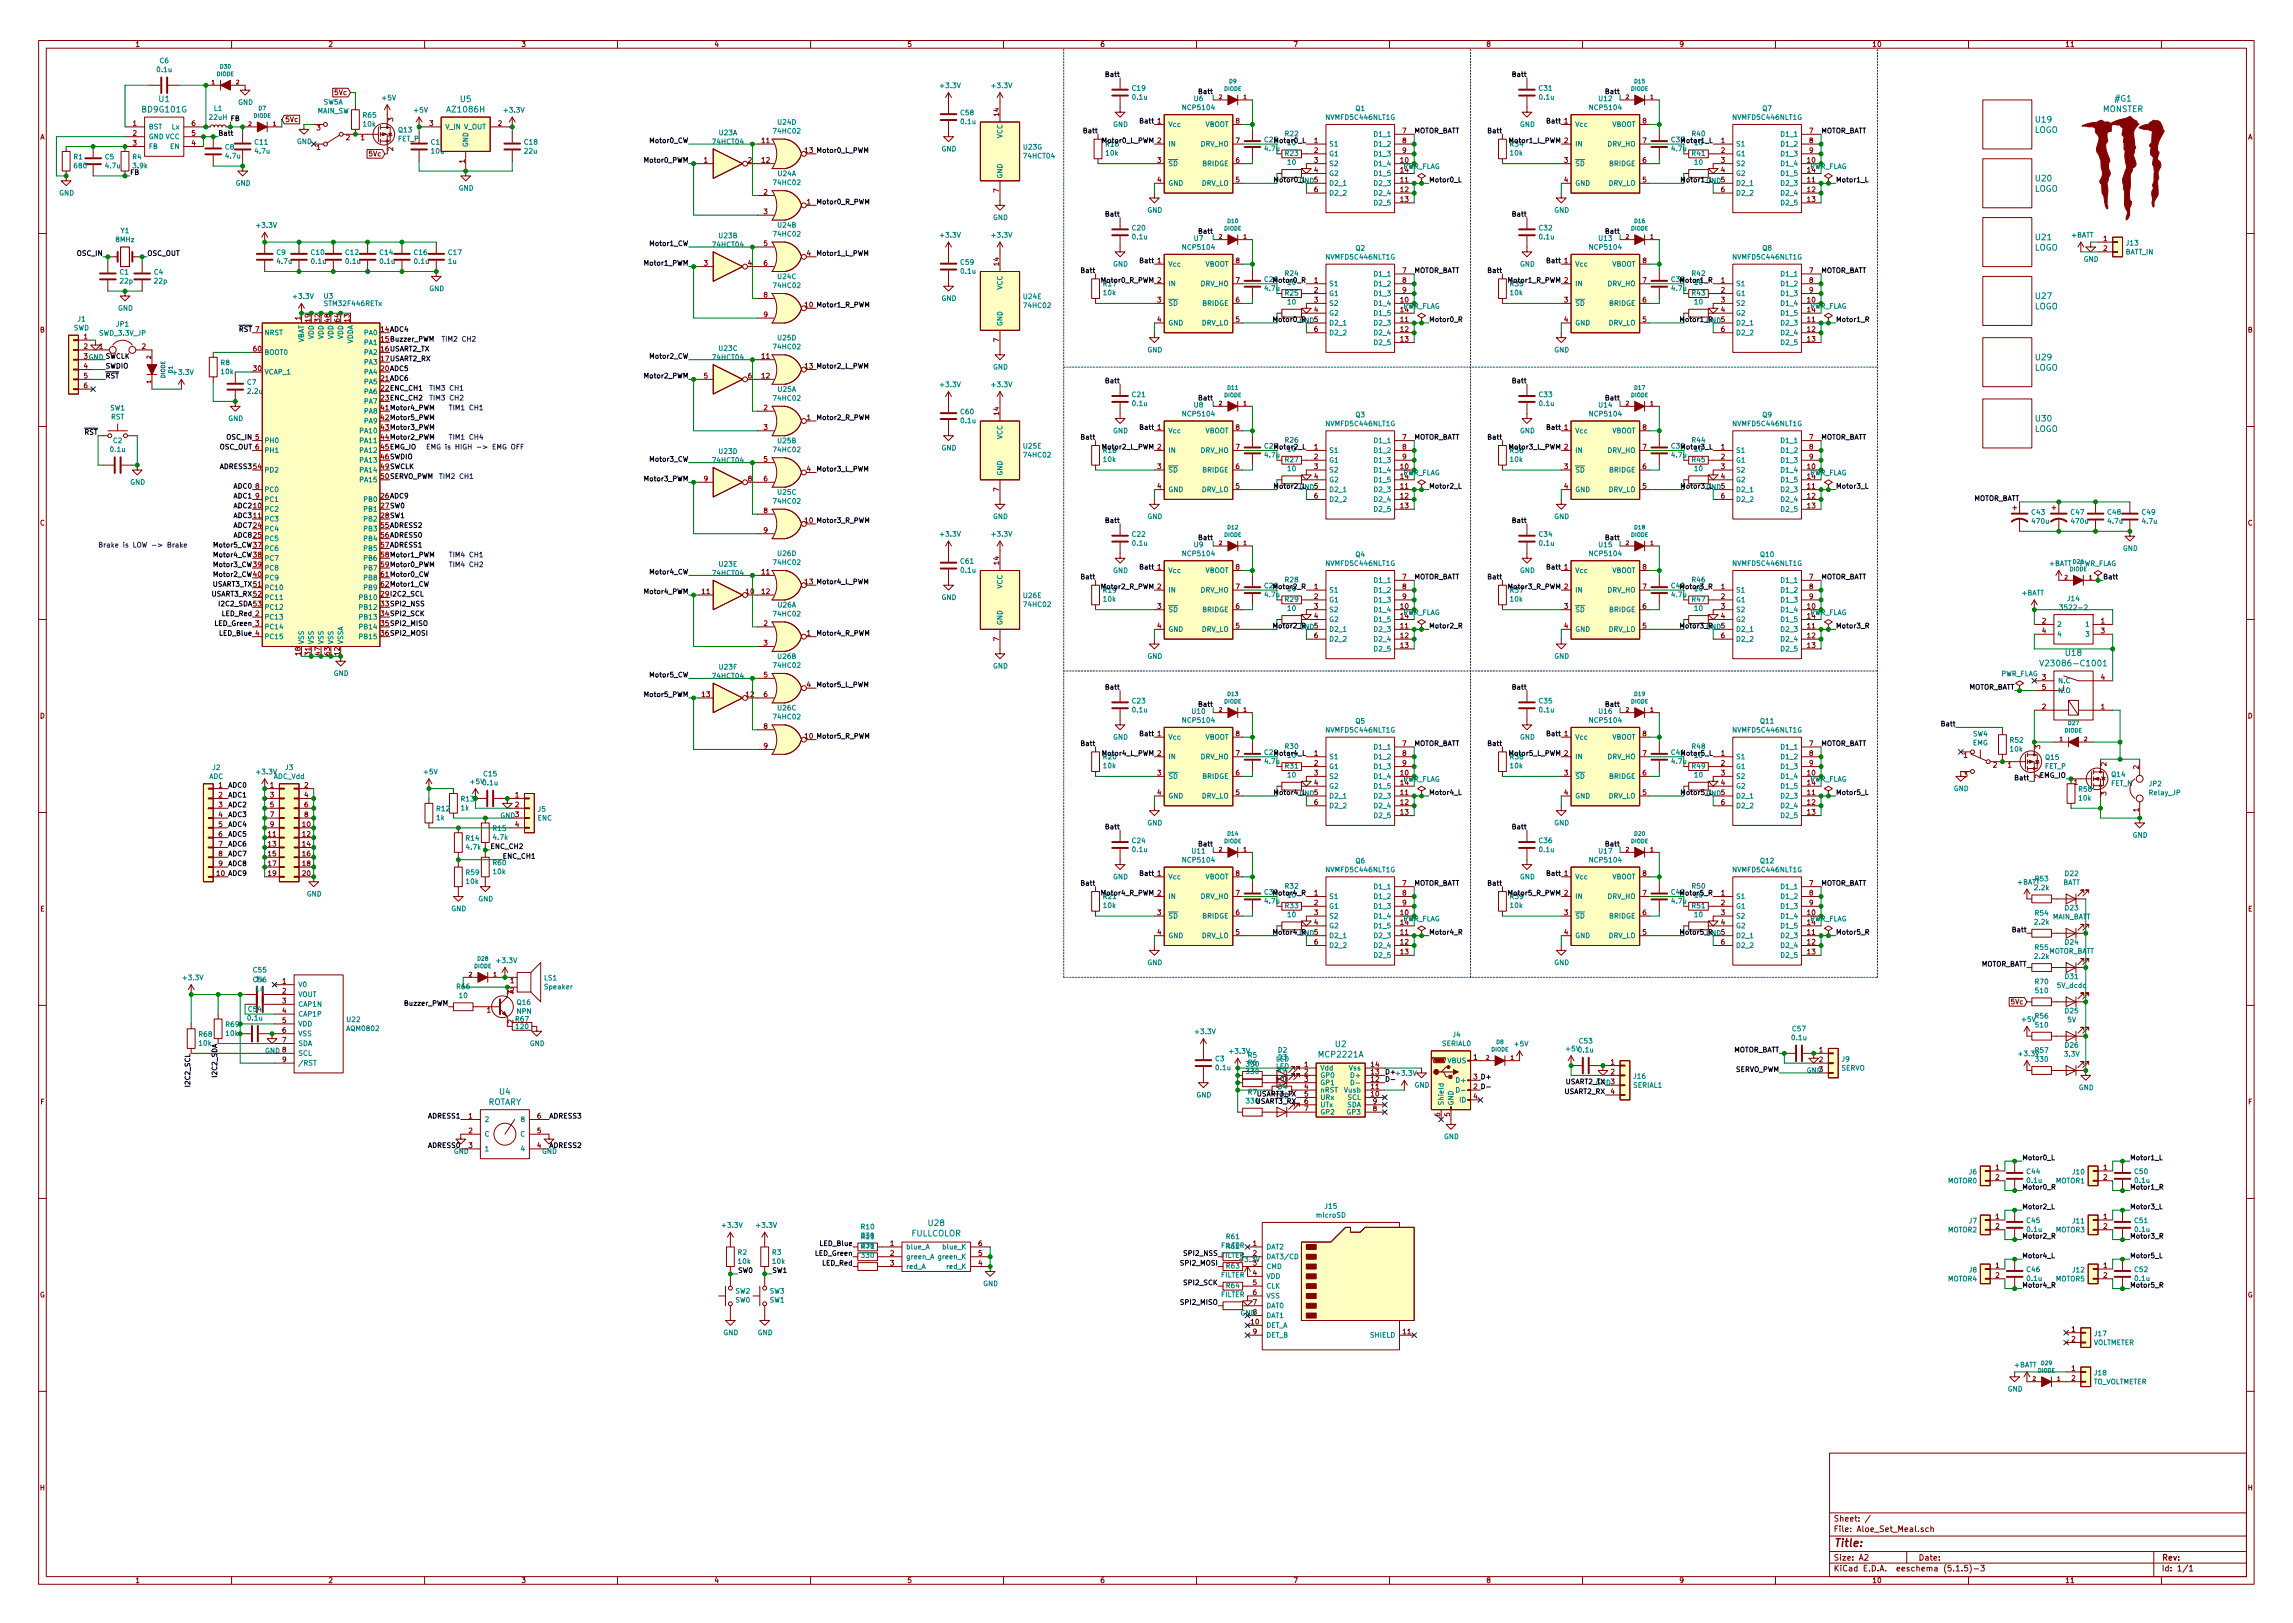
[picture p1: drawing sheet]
<svg xmlns="http://www.w3.org/2000/svg" width="297mm" height="210mm" viewBox="0 0 297 210" stroke-linecap="round" stroke-linejoin="round" font-family="sans-serif">
<defs><g id="words">
<text font-size="1.4" fill="#840000" x="237.5" y="200.4">Title:</text>
<g font-size="1.1" fill="#008484">
<text x="18.5" y="14.6">BD9G101G</text>
<text x="20.6" y="13.2">U1</text>
<text x="58.1" y="14.6">AZ1086H</text>
<text x="59.7" y="13.2">U5</text>
<text x="263.5" y="17.2">LOGO</text>
<text x="263.8" y="15.9">U19</text>
<text x="272.4" y="14.5">MONSTER</text>
<text x="274" y="13.2">#G1</text>
<text x="263.8" y="23.5">U20</text>
<text x="263.5" y="24.8">LOGO</text>
<text x="263.5" y="32.5">LOGO</text>
<text x="263.8" y="31.1">U21</text>
<text x="263.5" y="40.1">LOGO</text>
<text x="263.8" y="38.7">U27</text>
<text x="263.8" y="46.7">U29</text>
<text x="263.5" y="48">LOGO</text>
<text x="263.5" y="56">LOGO</text>
<text x="263.8" y="54.6">U30</text>
<text x="265" y="86.3">V23086-C1001</text>
<text x="267.6" y="85">U18</text>
<text x="170.9" y="137">MCP2221A</text>
<text x="173" y="135.6">U2</text>
<text x="63.2" y="143.1">ROTARY</text>
<text x="64.7" y="141.8">U4</text>
<text x="118" y="160.2">FULLCOLOR</text>
<text x="120.3" y="158.8">U28</text>
</g>
<g font-size="1" fill="#840000">
<text x="237.5" y="197.1">Sheet: /</text>
<text x="237.5" y="203.6">KiCad E.D.A. eeschema (5.1.5)-3</text>
<text x="237.5" y="202.2">Size: A2</text>
<text x="237.5" y="198.5">File: Aloe_Set_Meal.sch</text>
<text x="248.5" y="202.2">Date:</text>
<text x="280" y="202.2">Rev:</text>
<text x="280" y="203.6">Id: 1/1</text>
</g>
<g font-size=".9" fill="#840000">
<text x="17.5" y="6.1">1</text>
<text x="42.5" y="6.1">2</text>
<text x="67.5" y="6.1">3</text>
<text x="92.5" y="6.1">4</text>
<text x="117.5" y="6.1">5</text>
<text x="142.5" y="6.1">6</text>
<text x="167.5" y="6.1">7</text>
<text x="192.5" y="6.1">8</text>
<text x="217.5" y="6.1">9</text>
<text x="242.5" y="6.1">10</text>
<text x="267.5" y="6.1">11</text>
<text x="17.2" y="16.3">1</text>
<text x="17.2" y="17.6">2</text>
<text x="24.8" y="17.6">5</text>
<text x="24.8" y="16.3">6</text>
<text x="36.9" y="15.8">5Vc</text>
<text x="41" y="16.9">3</text>
<text x="43.4" y="12.3">5Vc</text>
<text x="50.9" y="15.7" transform="rotate(-90 50.9 15.7)">3</text>
<text x="55.6" y="16.3">3</text>
<text x="64.5" y="16.3">2</text>
<text x="129.4" y="15" transform="rotate(-90 129.4 15)">14</text>
<text x="160.1" y="16">8</text>
<text x="181.7" y="17.3">7</text>
<text x="212.8" y="16">8</text>
<text x="234.4" y="17.3">7</text>
<text x="5.2" y="18.1">A</text>
<text x="17.2" y="18.9">3</text>
<text x="24.8" y="18.9">4</text>
<text x="41" y="19.4">1</text>
<text x="44.8" y="18.2">2</text>
<text x="46.7" y="18.2">1</text>
<text x="47.9" y="20.3">5Vc</text>
<text x="50.9" y="19.5" transform="rotate(-90 50.9 19.5)">2</text>
<text x="60.2" y="21.1" transform="rotate(-90 60.2 21.1)">1</text>
<text x="91.2" y="21.1">1</text>
<text x="96.9" y="21.1">2</text>
<text x="98.7" y="18.5">11</text>
<text x="98.7" y="21.1">12</text>
<text x="149.9" y="18.5">2</text>
<text x="149.9" y="21.1">3</text>
<text x="149.9" y="23.6">4</text>
<text x="160.1" y="23.6">5</text>
<text x="160.1" y="21.1">6</text>
<text x="160.1" y="18.5">7</text>
<text x="170.3" y="18.5">1</text>
<text x="170.3" y="19.8">2</text>
<text x="170.3" y="21.1">3</text>
<text x="170.3" y="22.3">4</text>
<text x="181.4" y="21.1">10</text>
<text x="181.4" y="23.6">11</text>
<text x="181.4" y="22.3">14</text>
<text x="181.7" y="18.5">8</text>
<text x="181.7" y="19.8">9</text>
<text x="202.6" y="18.5">2</text>
<text x="202.6" y="21.1">3</text>
<text x="202.6" y="23.6">4</text>
<text x="212.8" y="23.6">5</text>
<text x="212.8" y="21.1">6</text>
<text x="212.8" y="18.5">7</text>
<text x="223" y="18.5">1</text>
<text x="223" y="19.8">2</text>
<text x="223" y="21.1">3</text>
<text x="223" y="22.3">4</text>
<text x="234.1" y="21.1">10</text>
<text x="234.1" y="23.6">11</text>
<text x="234.1" y="22.3">14</text>
<text x="234.4" y="18.5">8</text>
<text x="234.4" y="19.8">9</text>
<text x="291.2" y="18.1">A</text>
<text x="98.9" y="25.2">2</text>
<text x="98.9" y="27.7">3</text>
<text x="104.5" y="26.5">1</text>
<text x="129.4" y="24.9" transform="rotate(-90 129.4 24.9)">7</text>
<text x="170.3" y="24.9">6</text>
<text x="181.4" y="24.9">12</text>
<text x="181.4" y="26.2">13</text>
<text x="223" y="24.9">6</text>
<text x="234.1" y="24.9">12</text>
<text x="234.1" y="26.2">13</text>
<text x="91.2" y="34.4">3</text>
<text x="96.9" y="34.4">4</text>
<text x="98.9" y="31.9">5</text>
<text x="98.9" y="34.4">6</text>
<text x="104.5" y="33.1">4</text>
<text x="129.4" y="34.4" transform="rotate(-90 129.4 34.4)">14</text>
<text x="160.1" y="34.1">8</text>
<text x="181.7" y="35.4">7</text>
<text x="212.8" y="34.1">8</text>
<text x="234.4" y="35.4">7</text>
<text x="272.5" y="31.2">1</text>
<text x="272.5" y="32.5">2</text>
<text x="38.9" y="41.4" transform="rotate(-90 38.9 41.4)">1</text>
<text x="40.2" y="41.7" transform="rotate(-90 40.2 41.7)">19</text>
<text x="41.5" y="41.7" transform="rotate(-90 41.5 41.7)">32</text>
<text x="42.7" y="41.7" transform="rotate(-90 42.7 41.7)">48</text>
<text x="44" y="41.7" transform="rotate(-90 44 41.7)">64</text>
<text x="45.3" y="41.7" transform="rotate(-90 45.3 41.7)">13</text>
<text x="98.9" y="38.5">8</text>
<text x="98.9" y="41.1">9</text>
<text x="149.9" y="39.2">3</text>
<text x="149.9" y="41.7">4</text>
<text x="160.1" y="41.7">5</text>
<text x="160.1" y="39.2">6</text>
<text x="160.1" y="36.6">7</text>
<text x="170.3" y="36.6">1</text>
<text x="170.3" y="37.9">2</text>
<text x="170.3" y="39.2">3</text>
<text x="170.3" y="40.4">4</text>
<text x="181.4" y="39.2">10</text>
<text x="181.4" y="41.7">11</text>
<text x="181.4" y="40.4">14</text>
<text x="181.7" y="36.6">8</text>
<text x="181.7" y="37.9">9</text>
<text x="202.6" y="39.2">3</text>
<text x="202.6" y="41.7">4</text>
<text x="212.8" y="41.7">5</text>
<text x="212.8" y="39.2">6</text>
<text x="212.8" y="36.6">7</text>
<text x="223" y="36.6">1</text>
<text x="223" y="37.9">2</text>
<text x="223" y="39.2">3</text>
<text x="223" y="40.4">4</text>
<text x="234.1" y="39.2">10</text>
<text x="234.1" y="41.7">11</text>
<text x="234.1" y="40.4">14</text>
<text x="234.4" y="36.6">8</text>
<text x="234.4" y="37.9">9</text>
<text x="5.2" y="43.1">B</text>
<text x="10.9" y="43.9">1</text>
<text x="10.9" y="45.2">2</text>
<text x="10.9" y="47.7">4</text>
<text x="12.9" y="45.2">1</text>
<text x="18.4" y="45.2">2</text>
<text x="32.9" y="45.5">60</text>
<text x="98.7" y="46.5">11</text>
<text x="129.4" y="44.3" transform="rotate(-90 129.4 44.3)">7</text>
<text x="170.3" y="43">6</text>
<text x="181.4" y="43">12</text>
<text x="181.4" y="44.3">13</text>
<text x="223" y="43">6</text>
<text x="234.1" y="43">12</text>
<text x="234.1" y="44.3">13</text>
<text x="291.2" y="43.1">B</text>
<text x="10.9" y="49">5</text>
<text x="10.9" y="50.3">6</text>
<text x="32.9" y="48.1">30</text>
<text x="91.2" y="49">5</text>
<text x="96.9" y="49">6</text>
<text x="98.7" y="49">12</text>
<text x="98.9" y="53.1">2</text>
<text x="129.4" y="53.8" transform="rotate(-90 129.4 53.8)">14</text>
<text x="98.9" y="55.7">3</text>
<text x="98.9" y="59.8">5</text>
<text x="104.5" y="54.4">1</text>
<text x="149.9" y="58.2">2</text>
<text x="160.1" y="58.2">7</text>
<text x="160.1" y="55.7">8</text>
<text x="170.3" y="58.2">1</text>
<text x="170.3" y="59.5">2</text>
<text x="181.7" y="57">7</text>
<text x="181.7" y="58.2">8</text>
<text x="181.7" y="59.5">9</text>
<text x="202.6" y="58.2">2</text>
<text x="212.8" y="58.2">7</text>
<text x="212.8" y="55.7">8</text>
<text x="223" y="58.2">1</text>
<text x="223" y="59.5">2</text>
<text x="234.4" y="57">7</text>
<text x="234.4" y="58.2">8</text>
<text x="234.4" y="59.5">9</text>
<text x="32.9" y="65.8">10</text>
<text x="32.9" y="60.8">54</text>
<text x="33.1" y="63.3">8</text>
<text x="33.1" y="64.6">9</text>
<text x="91.2" y="62.4">9</text>
<text x="96.9" y="62.4">8</text>
<text x="98.9" y="62.4">6</text>
<text x="104.5" y="61.1">4</text>
<text x="129.4" y="63.7" transform="rotate(-90 129.4 63.7)">7</text>
<text x="149.9" y="60.8">3</text>
<text x="149.9" y="63.3">4</text>
<text x="160.1" y="63.3">5</text>
<text x="160.1" y="60.8">6</text>
<text x="170.3" y="60.8">3</text>
<text x="170.3" y="62">4</text>
<text x="170.3" y="64.6">6</text>
<text x="181.4" y="60.8">10</text>
<text x="181.4" y="63.3">11</text>
<text x="181.4" y="64.6">12</text>
<text x="181.4" y="65.8">13</text>
<text x="181.4" y="62">14</text>
<text x="202.6" y="60.8">3</text>
<text x="202.6" y="63.3">4</text>
<text x="212.8" y="63.3">5</text>
<text x="212.8" y="60.8">6</text>
<text x="223" y="60.8">3</text>
<text x="223" y="62">4</text>
<text x="223" y="64.6">6</text>
<text x="234.1" y="60.8">10</text>
<text x="234.1" y="63.3">11</text>
<text x="234.1" y="64.6">12</text>
<text x="234.1" y="65.8">13</text>
<text x="234.1" y="62">14</text>
<text x="5.2" y="68.1">C</text>
<text x="32.9" y="67.1">11</text>
<text x="32.9" y="68.4">24</text>
<text x="32.9" y="69.7">25</text>
<text x="98.9" y="66.5">8</text>
<text x="98.9" y="69">9</text>
<text x="291.2" y="68.1">C</text>
<text x="91" y="77">11</text>
<text x="96.7" y="77">10</text>
<text x="98.7" y="74.4">11</text>
<text x="98.7" y="77">12</text>
<text x="129.4" y="73.1" transform="rotate(-90 129.4 73.1)">14</text>
<text x="160.1" y="76.3">7</text>
<text x="160.1" y="73.8">8</text>
<text x="170.3" y="76.3">1</text>
<text x="170.3" y="77.6">2</text>
<text x="181.7" y="75.1">7</text>
<text x="181.7" y="76.3">8</text>
<text x="181.7" y="77.6">9</text>
<text x="212.8" y="76.3">7</text>
<text x="212.8" y="73.8">8</text>
<text x="223" y="76.3">1</text>
<text x="223" y="77.6">2</text>
<text x="234.4" y="75.1">7</text>
<text x="234.4" y="76.3">8</text>
<text x="234.4" y="77.6">9</text>
<text x="98.9" y="81.1">2</text>
<text x="98.9" y="83.6">3</text>
<text x="104.5" y="82.4">1</text>
<text x="129.4" y="83" transform="rotate(-90 129.4 83)">7</text>
<text x="149.9" y="78.9">3</text>
<text x="149.9" y="81.4">4</text>
<text x="160.1" y="81.4">5</text>
<text x="160.1" y="78.9">6</text>
<text x="170.3" y="78.9">3</text>
<text x="170.3" y="80.1">4</text>
<text x="170.3" y="82.7">6</text>
<text x="181.4" y="78.9">10</text>
<text x="181.4" y="81.4">11</text>
<text x="181.4" y="82.7">12</text>
<text x="181.4" y="83.9">13</text>
<text x="181.4" y="80.1">14</text>
<text x="202.6" y="78.9">3</text>
<text x="202.6" y="81.4">4</text>
<text x="212.8" y="81.4">5</text>
<text x="212.8" y="78.9">6</text>
<text x="223" y="78.9">3</text>
<text x="223" y="80.1">4</text>
<text x="223" y="82.7">6</text>
<text x="234.1" y="78.9">10</text>
<text x="234.1" y="81.4">11</text>
<text x="234.1" y="82.7">12</text>
<text x="234.1" y="83.9">13</text>
<text x="234.1" y="80.1">14</text>
<text x="264.6" y="80.8">2</text>
<text x="264.6" y="82">4</text>
<text x="272.2" y="80.8">1</text>
<text x="272.2" y="82">3</text>
<text x="38.9" y="84.9" transform="rotate(-90 38.9 84.9)">18</text>
<text x="40.2" y="84.9" transform="rotate(-90 40.2 84.9)">31</text>
<text x="41.5" y="84.9" transform="rotate(-90 41.5 84.9)">47</text>
<text x="42.7" y="84.9" transform="rotate(-90 42.7 84.9)">63</text>
<text x="44" y="84.9" transform="rotate(-90 44 84.9)">12</text>
<text x="98.9" y="87.8">5</text>
<text x="104.5" y="89">4</text>
<text x="264.6" y="88.1">3</text>
<text x="264.6" y="89.3">5</text>
<text x="272.2" y="88.1">4</text>
<text x="5.2" y="93.1">D</text>
<text x="91" y="90.3">13</text>
<text x="96.7" y="90.3">12</text>
<text x="98.9" y="90.3">6</text>
<text x="98.9" y="94.4">8</text>
<text x="160.1" y="95.4">8</text>
<text x="212.8" y="95.4">8</text>
<text x="264.6" y="91.9">2</text>
<text x="272.2" y="91.9">1</text>
<text x="291.2" y="93.1">D</text>
<text x="98.9" y="97">9</text>
<text x="149.9" y="97.9">2</text>
<text x="149.9" y="100.5">3</text>
<text x="160.1" y="100.5">6</text>
<text x="160.1" y="97.9">7</text>
<text x="170.3" y="97.9">1</text>
<text x="170.3" y="99.2">2</text>
<text x="170.3" y="100.5">3</text>
<text x="170.3" y="101.7">4</text>
<text x="181.4" y="100.5">10</text>
<text x="181.4" y="101.7">14</text>
<text x="181.7" y="96.6">7</text>
<text x="181.7" y="97.9">8</text>
<text x="181.7" y="99.2">9</text>
<text x="202.6" y="97.9">2</text>
<text x="202.6" y="100.5">3</text>
<text x="212.8" y="100.5">6</text>
<text x="212.8" y="97.9">7</text>
<text x="223" y="97.9">1</text>
<text x="223" y="99.2">2</text>
<text x="223" y="100.5">3</text>
<text x="223" y="101.7">4</text>
<text x="234.1" y="100.5">10</text>
<text x="234.1" y="101.7">14</text>
<text x="234.4" y="96.6">7</text>
<text x="234.4" y="97.9">8</text>
<text x="234.4" y="99.2">9</text>
<text x="254.4" y="98.2">1</text>
<text x="254.4" y="100.7">3</text>
<text x="258.2" y="99.4">2</text>
<text x="260.1" y="99.4">1</text>
<text x="264.3" y="97" transform="rotate(-90 264.3 97)">3</text>
<text x="268.7" y="101.7">1</text>
<text x="272.9" y="99.2" transform="rotate(-90 272.9 99.2)">2</text>
<text x="277.1" y="99.6" transform="rotate(-90 277.1 99.6)">2</text>
<text x="28.3" y="102">1</text>
<text x="28.3" y="103.3">2</text>
<text x="28.3" y="104.6">3</text>
<text x="28.3" y="105.8">4</text>
<text x="28.3" y="107.1">5</text>
<text x="35" y="102">1</text>
<text x="35" y="103.3">3</text>
<text x="35" y="104.6">5</text>
<text x="35" y="105.8">7</text>
<text x="35" y="107.1">9</text>
<text x="39.2" y="107.1">10</text>
<text x="39.4" y="102">2</text>
<text x="39.4" y="103.3">4</text>
<text x="39.4" y="104.6">6</text>
<text x="39.4" y="105.8">8</text>
<text x="66.8" y="103.3">1</text>
<text x="66.8" y="104.6">2</text>
<text x="66.8" y="107.1">4</text>
<text x="149.9" y="103">4</text>
<text x="160.1" y="103">5</text>
<text x="170.3" y="104.3">6</text>
<text x="181.4" y="103">11</text>
<text x="181.4" y="104.3">12</text>
<text x="181.4" y="105.5">13</text>
<text x="202.6" y="103">4</text>
<text x="212.8" y="103">5</text>
<text x="223" y="104.3">6</text>
<text x="234.1" y="103">11</text>
<text x="234.1" y="104.3">12</text>
<text x="234.1" y="105.5">13</text>
<text x="272.9" y="103" transform="rotate(-90 272.9 103)">3</text>
<text x="277.1" y="105.2" transform="rotate(-90 277.1 105.2)">1</text>
<text x="28.3" y="108.4">6</text>
<text x="28.3" y="109.7">7</text>
<text x="28.3" y="110.9">8</text>
<text x="28.3" y="112.2">9</text>
<text x="34.8" y="108.4">11</text>
<text x="34.8" y="109.7">13</text>
<text x="34.8" y="110.9">15</text>
<text x="34.8" y="112.2">17</text>
<text x="34.8" y="113.5">19</text>
<text x="39.2" y="108.4">12</text>
<text x="39.2" y="109.7">14</text>
<text x="39.2" y="110.9">16</text>
<text x="39.2" y="112.2">18</text>
<text x="39.2" y="113.5">20</text>
<text x="160.1" y="113.5">8</text>
<text x="212.8" y="113.5">8</text>
<text x="5.2" y="118.1">E</text>
<text x="149.9" y="118.5">3</text>
<text x="160.1" y="118.5">6</text>
<text x="160.1" y="116">7</text>
<text x="170.3" y="116">1</text>
<text x="170.3" y="117.3">2</text>
<text x="170.3" y="118.5">3</text>
<text x="170.3" y="119.8">4</text>
<text x="181.4" y="118.5">10</text>
<text x="181.4" y="119.8">14</text>
<text x="181.7" y="114.7">7</text>
<text x="181.7" y="116">8</text>
<text x="181.7" y="117.3">9</text>
<text x="202.6" y="118.5">3</text>
<text x="212.8" y="118.5">6</text>
<text x="212.8" y="116">7</text>
<text x="223" y="116">1</text>
<text x="223" y="117.3">2</text>
<text x="223" y="118.5">3</text>
<text x="223" y="119.8">4</text>
<text x="234.1" y="118.5">10</text>
<text x="234.1" y="119.8">14</text>
<text x="234.4" y="114.7">7</text>
<text x="234.4" y="116">8</text>
<text x="234.4" y="117.3">9</text>
<text x="291.2" y="118.1">E</text>
<text x="149.9" y="121.1">4</text>
<text x="160.1" y="121.1">5</text>
<text x="170.3" y="122.4">6</text>
<text x="181.4" y="121.1">11</text>
<text x="181.4" y="122.4">12</text>
<text x="181.4" y="123.6">13</text>
<text x="202.6" y="121.1">4</text>
<text x="212.8" y="121.1">5</text>
<text x="223" y="122.4">6</text>
<text x="234.1" y="121.1">11</text>
<text x="234.1" y="122.4">12</text>
<text x="234.1" y="123.6">13</text>
<text x="36.6" y="127.4">1</text>
<text x="36.6" y="128.7">2</text>
<text x="36.6" y="130">3</text>
<text x="36.6" y="131.2">4</text>
<text x="63.1" y="131.2">1</text>
<text x="66.1" y="127.4">1</text>
<text x="66.1" y="128.6">2</text>
<text x="66.5" y="128.8" transform="rotate(-90 66.5 128.8)">3</text>
<text x="260.6" y="130.1">5Vc</text>
<text x="34.3" y="136.5">GND 8</text>
<text x="36.6" y="132.5">5</text>
<text x="36.6" y="133.8">6</text>
<text x="36.6" y="135.1">7</text>
<text x="36.6" y="137.6">9</text>
<text x="66.5" y="132.6" transform="rotate(-90 66.5 132.6)">2</text>
<text x="190.9" y="137.3">1</text>
<text x="208.7" y="137.9">1</text>
<text x="235.7" y="136.3">1</text>
<text x="235.7" y="137.6">2</text>
<text x="5.2" y="143.1">F</text>
<text x="165.3" y="140.1">10k</text>
<text x="169" y="138.2">1</text>
<text x="169" y="139.2">2</text>
<text x="169" y="140.1">3</text>
<text x="169" y="141.1">4</text>
<text x="169" y="142">5</text>
<text x="169" y="143">6</text>
<text x="169" y="143.9">7</text>
<text x="177.6" y="142">10</text>
<text x="177.6" y="141.1">11</text>
<text x="177.6" y="140.1">12</text>
<text x="177.6" y="139.2">13</text>
<text x="177.6" y="138.2">14</text>
<text x="177.9" y="143.9">8</text>
<text x="177.9" y="143">9</text>
<text x="190.9" y="142.4">4</text>
<text x="208.7" y="139.2">2</text>
<text x="208.7" y="141.7">4</text>
<text x="291.2" y="143.1">F</text>
<text x="60.7" y="144.9">1</text>
<text x="60.7" y="146.8">2</text>
<text x="60.7" y="148.7">3</text>
<text x="69.6" y="148.7">4</text>
<text x="69.6" y="146.8">5</text>
<text x="69.6" y="144.9">6</text>
<text x="186.6" y="144.6" transform="rotate(-90 186.6 144.6)">6</text>
<text x="187.8" y="144.6" transform="rotate(-90 187.8 144.6)">5</text>
<text x="258.5" y="151.6">1</text>
<text x="258.5" y="152.8">2</text>
<text x="272.5" y="151.6">1</text>
<text x="272.5" y="152.8">2</text>
<text x="115.3" y="161.4">1</text>
<text x="126.8" y="161.4">6</text>
<text x="162.3" y="161.4">1</text>
<text x="258.5" y="157.9">1</text>
<text x="258.5" y="159.2">2</text>
<text x="272.5" y="157.9">1</text>
<text x="272.5" y="159.2">2</text>
<text x="115.3" y="162.7">2</text>
<text x="115.3" y="164">3</text>
<text x="126.8" y="164">4</text>
<text x="126.8" y="162.7">5</text>
<text x="162.3" y="162.7">2</text>
<text x="162.3" y="164">3</text>
<text x="162.3" y="165.2">4</text>
<text x="162.3" y="166.5">5</text>
<text x="162.3" y="167.8">6</text>
<text x="258.5" y="164.3">1</text>
<text x="258.5" y="165.5">2</text>
<text x="272.5" y="164.3">1</text>
<text x="272.5" y="165.5">2</text>
<text x="5.2" y="168.1">G</text>
<text x="162.1" y="171.6">10</text>
<text x="162.3" y="169">7</text>
<text x="162.3" y="172.8">9</text>
<text x="181.8" y="172.8">11</text>
<text x="268.4" y="172.5">1</text>
<text x="268.4" y="173.8">2</text>
<text x="291.2" y="168.1">G</text>
<text x="268.4" y="177.6">1</text>
<text x="268.4" y="178.9">2</text>
<text x="5.2" y="193.1">H</text>
<text x="291.2" y="193.1">H</text>
<text x="17.5" y="205.1">1</text>
<text x="42.5" y="205.1">2</text>
<text x="67.5" y="205.1">3</text>
<text x="92.5" y="205.1">4</text>
<text x="117.5" y="205.1">5</text>
<text x="142.5" y="205.1">6</text>
<text x="167.5" y="205.1">7</text>
<text x="192.5" y="205.1">8</text>
<text x="217.5" y="205.1">9</text>
<text x="242.5" y="205.1">10</text>
<text x="267.5" y="205.1">11</text>
</g>
<g font-size=".9" fill="#008484">
<text x="20.4" y="9.3">0.1u</text>
<text x="20.7" y="8.2">C6</text>
<text x="121.9" y="11.4">+3.3V</text>
<text x="128.6" y="11.4">+3.3V</text>
<text x="146.7" y="11.8">C19</text>
<text x="199.4" y="11.8">C31</text>
<text x="19.2" y="16.8">BST</text>
<text x="22.3" y="16.8">Lx</text>
<text x="27.7" y="14.4">L1</text>
<text x="30.8" y="13.6">GND</text>
<text x="41.1" y="14.7">MAIN_SW</text>
<text x="41.9" y="13.5">SW5A</text>
<text x="47.1" y="15.2">R65</text>
<text x="47.1" y="16.4">10k</text>
<text x="49.6" y="13">+5V</text>
<text x="51.7" y="17.2">Q13</text>
<text x="53.7" y="14.6">+5V</text>
<text x="57.7" y="16.8">V_IN V_OUT</text>
<text x="65.4" y="14.6">+3.3V</text>
<text x="93.2" y="17.5">U23A</text>
<text x="100.3" y="17.3">74HC02</text>
<text x="100.8" y="16.1">U24D</text>
<text x="124.5" y="14.9">C58</text>
<text x="124.5" y="16.1">0.1u</text>
<text x="129.9" y="17.9" transform="rotate(-90 129.9 17.9)">VCC</text>
<text x="144.2" y="16.4">GND</text>
<text x="146.8" y="12.9">0.1u</text>
<text x="151.3" y="16.4">Vcc</text>
<text x="153.3" y="14.3">NCP5104</text>
<text x="154.7" y="13.1">U6</text>
<text x="156" y="16.4">VBOOT</text>
<text x="166.5" y="17.6">R22</text>
<text x="171.9" y="15.5">NVMFD5C446NLT1G</text>
<text x="175.6" y="14.4">Q1</text>
<text x="178.2" y="17.7">D1_1</text>
<text x="196.9" y="16.4">GND</text>
<text x="199.5" y="12.9">0.1u</text>
<text x="204" y="16.4">Vcc</text>
<text x="206" y="14.3">NCP5104</text>
<text x="207.1" y="13.1">U12</text>
<text x="208.7" y="16.4">VBOOT</text>
<text x="219.2" y="17.6">R40</text>
<text x="224.6" y="15.5">NVMFD5C446NLT1G</text>
<text x="228.3" y="14.4">Q7</text>
<text x="230.9" y="17.7">D1_1</text>
<text x="9.6" y="20.6">R1</text>
<text x="9.7" y="21.8">680</text>
<text x="13.6" y="20.6">C5</text>
<text x="13.7" y="21.8">4.7u</text>
<text x="17.2" y="20.6">R4</text>
<text x="17.3" y="21.8">3.9k</text>
<text x="19.2" y="18">GND VCC</text>
<text x="19.2" y="19.3">FB</text>
<text x="22.1" y="19.3">EN</text>
<text x="29.2" y="19.4">C8</text>
<text x="29.3" y="20.5">4.7u</text>
<text x="33" y="18.7">C11</text>
<text x="33.1" y="19.9">4.7u</text>
<text x="38.5" y="18.7">GND</text>
<text x="51.5" y="18.3">FET_P</text>
<text x="55.9" y="18.7">C13</text>
<text x="55.9" y="19.9">10u</text>
<text x="60.6" y="19.1" transform="rotate(-90 60.6 19.1)">GND</text>
<text x="68" y="18.7">C18</text>
<text x="68" y="19.9">22u</text>
<text x="92.4" y="18.7">74HCT04</text>
<text x="100.3" y="24">74HC02</text>
<text x="100.8" y="22.8">U24A</text>
<text x="122" y="19.6">GND</text>
<text x="129.9" y="23.2" transform="rotate(-90 129.9 23.2)">GND</text>
<text x="132.6" y="19.4">U23G</text>
<text x="132.7" y="20.5">74HCT04</text>
<text x="143.3" y="20.1">10k</text>
<text x="151.3" y="19">IN</text>
<text x="151.3" y="21.5">SD</text>
<text x="155.5" y="19">DRV_HO</text>
<text x="155.8" y="21.5">BRIDGE</text>
<text x="163.9" y="19.6">4.7u</text>
<text x="166.5" y="20.2">R23</text>
<text x="166.8" y="21.3">10</text>
<text x="172.1" y="19">S1</text>
<text x="172.1" y="20.3">G1</text>
<text x="172.1" y="21.5">S2</text>
<text x="172.1" y="22.8">G2</text>
<text x="178.2" y="21.5">D1_4</text>
<text x="178.2" y="19">D1_2</text>
<text x="178.2" y="20.3">D1_3</text>
<text x="178.2" y="22.8">D1_5</text>
<text x="195.7" y="20.1">10k</text>
<text x="204" y="19">IN</text>
<text x="204" y="21.5">SD</text>
<text x="208.2" y="19">DRV_HO</text>
<text x="208.5" y="21.5">BRIDGE</text>
<text x="216.6" y="19.6">4.7u</text>
<text x="219.2" y="20.2">R41</text>
<text x="219.5" y="21.3">10</text>
<text x="224.9" y="19">S1</text>
<text x="224.9" y="20.3">G1</text>
<text x="224.9" y="21.5">S2</text>
<text x="224.9" y="22.8">G2</text>
<text x="230.9" y="21.5">D1_4</text>
<text x="230.9" y="19">D1_2</text>
<text x="230.9" y="20.3">D1_3</text>
<text x="230.9" y="22.8">D1_5</text>
<text x="7.7" y="25.3">GND</text>
<text x="30.5" y="24.1">GND</text>
<text x="33.3" y="29.5">+3.3V</text>
<text x="59.4" y="24.7">GND</text>
<text x="100.8" y="29.5">U24B</text>
<text x="128.6" y="28.5">GND</text>
<text x="146.7" y="29.9">C20</text>
<text x="148.6" y="27.6">GND</text>
<text x="151.3" y="24.1">GND</text>
<text x="155.6" y="24.1">DRV_LO</text>
<text x="172.1" y="24.1">D2_1</text>
<text x="172.1" y="25.3">D2_2</text>
<text x="178.2" y="24.1">D2_3</text>
<text x="178.2" y="25.3">D2_4</text>
<text x="178.2" y="26.6">D2_5</text>
<text x="199.4" y="29.9">C32</text>
<text x="201.3" y="27.6">GND</text>
<text x="204" y="24.1">GND</text>
<text x="208.3" y="24.1">DRV_LO</text>
<text x="224.9" y="24.1">D2_1</text>
<text x="224.9" y="25.3">D2_2</text>
<text x="230.9" y="24.1">D2_3</text>
<text x="230.9" y="25.3">D2_4</text>
<text x="230.9" y="26.6">D2_5</text>
<text x="15" y="31.4">8MHz</text>
<text x="15.5" y="35.6">C1</text>
<text x="15.7" y="30.2">Y1</text>
<text x="20" y="35.6">C4</text>
<text x="35.9" y="33">C9</text>
<text x="36" y="34.2">4.7u</text>
<text x="40.3" y="33">C10</text>
<text x="40.4" y="34.2">0.1u</text>
<text x="44.8" y="33">C12</text>
<text x="44.8" y="34.2">0.1u</text>
<text x="49.2" y="33">C14</text>
<text x="49.3" y="34.2">0.1u</text>
<text x="53.7" y="33">C16</text>
<text x="53.7" y="34.2">0.1u</text>
<text x="58.1" y="34.2">1u</text>
<text x="58.1" y="33">C17</text>
<text x="92.4" y="32">74HCT04</text>
<text x="93.2" y="30.9">U23B</text>
<text x="100.3" y="30.6">74HC02</text>
<text x="121.9" y="30.8">+3.3V</text>
<text x="124.5" y="34.3">C59</text>
<text x="124.5" y="35.5">0.1u</text>
<text x="128.6" y="30.8">+3.3V</text>
<text x="144.2" y="34.5">GND</text>
<text x="146.8" y="31">0.1u</text>
<text x="151.3" y="34.5">Vcc</text>
<text x="153.3" y="32.4">NCP5104</text>
<text x="154.7" y="31.2">U7</text>
<text x="156" y="34.5">VBOOT</text>
<text x="166.5" y="35.7">R24</text>
<text x="171.9" y="33.6">NVMFD5C446NLT1G</text>
<text x="175.6" y="32.5">Q2</text>
<text x="178.2" y="35.8">D1_1</text>
<text x="196.9" y="34.5">GND</text>
<text x="199.5" y="31">0.1u</text>
<text x="204" y="34.5">Vcc</text>
<text x="206" y="32.4">NCP5104</text>
<text x="207.1" y="31.2">U13</text>
<text x="208.7" y="34.5">VBOOT</text>
<text x="219.2" y="35.7">R42</text>
<text x="224.6" y="33.6">NVMFD5C446NLT1G</text>
<text x="228.3" y="32.5">Q8</text>
<text x="230.9" y="35.8">D1_1</text>
<text x="268.3" y="30.8">+BATT</text>
<text x="269.9" y="33.9">GND</text>
<text x="275.3" y="33">BATT_IN</text>
<text x="275.5" y="31.8">J13</text>
<text x="10.1" y="41.7">J1</text>
<text x="15.3" y="40.3">GND</text>
<text x="15.6" y="36.7">22p</text>
<text x="20" y="36.7">22p</text>
<text x="38.1" y="38.7">+3.3V</text>
<text x="42" y="38.7">U3</text>
<text x="42.2" y="39.6">STM32F446RETx</text>
<text x="55.6" y="37.7">GND</text>
<text x="100.3" y="37.3">74HC02</text>
<text x="100.8" y="36.2">U24C</text>
<text x="122" y="39">GND</text>
<text x="129.9" y="37.5" transform="rotate(-90 129.9 37.5)">VCC</text>
<text x="132.6" y="38.7">U24E</text>
<text x="132.7" y="39.9">74HC02</text>
<text x="143" y="38.2">10k</text>
<text x="151.3" y="37.1">IN</text>
<text x="151.3" y="39.6">SD</text>
<text x="155.5" y="37.1">DRV_HO</text>
<text x="155.8" y="39.6">BRIDGE</text>
<text x="163.9" y="37.7">4.7u</text>
<text x="166.5" y="38.3">R25</text>
<text x="166.8" y="39.4">10</text>
<text x="172.1" y="37.1">S1</text>
<text x="172.1" y="38.3">G1</text>
<text x="172.1" y="39.6">S2</text>
<text x="172.1" y="40.9">G2</text>
<text x="178.2" y="39.6">D1_4</text>
<text x="178.2" y="37.1">D1_2</text>
<text x="178.2" y="38.3">D1_3</text>
<text x="178.2" y="40.9">D1_5</text>
<text x="195.7" y="38.2">10k</text>
<text x="204" y="37.1">IN</text>
<text x="204" y="39.6">SD</text>
<text x="208.2" y="37.1">DRV_HO</text>
<text x="208.5" y="39.6">BRIDGE</text>
<text x="216.6" y="37.7">4.7u</text>
<text x="219.2" y="38.3">R43</text>
<text x="219.5" y="39.4">10</text>
<text x="224.9" y="37.1">S1</text>
<text x="224.9" y="38.3">G1</text>
<text x="224.9" y="39.6">S2</text>
<text x="224.9" y="40.9">G2</text>
<text x="230.9" y="39.6">D1_4</text>
<text x="230.9" y="37.1">D1_2</text>
<text x="230.9" y="38.3">D1_3</text>
<text x="230.9" y="40.9">D1_5</text>
<text x="9.5" y="42.8">SWD</text>
<text x="12.9" y="43.5">SWD_3.3V_JP</text>
<text x="15.1" y="42.3">JP1</text>
<text x="28.6" y="47.3">R8</text>
<text x="34.2" y="46">BOOT0</text>
<text x="34.2" y="43.4">NRST</text>
<text x="39.4" y="44.5" transform="rotate(-90 39.4 44.5)">VBAT</text>
<text x="40.6" y="44" transform="rotate(-90 40.6 44)">VDD</text>
<text x="41.9" y="44" transform="rotate(-90 41.9 44)">VDD</text>
<text x="43.2" y="44" transform="rotate(-90 43.2 44)">VDD</text>
<text x="44.4" y="44" transform="rotate(-90 44.4 44)">VDD</text>
<text x="45.7" y="44.6" transform="rotate(-90 45.7 44.6)">VDDA</text>
<text x="47.2" y="43.4">PA0</text>
<text x="47.2" y="44.7">PA1</text>
<text x="47.2" y="46">PA2</text>
<text x="47.2" y="47.2">PA3</text>
<text x="92.4" y="46.6">74HCT04</text>
<text x="93.2" y="45.5">U23C</text>
<text x="100.3" y="45.2">74HC02</text>
<text x="100.8" y="44.1">U25D</text>
<text x="128.6" y="47.9">GND</text>
<text x="129.9" y="42.3" transform="rotate(-90 129.9 42.3)">GND</text>
<text x="148.6" y="45.7">GND</text>
<text x="151.3" y="42.2">GND</text>
<text x="155.6" y="42.2">DRV_LO</text>
<text x="172.1" y="42.2">D2_1</text>
<text x="172.1" y="43.4">D2_2</text>
<text x="178.2" y="42.2">D2_3</text>
<text x="178.2" y="43.4">D2_4</text>
<text x="178.2" y="44.7">D2_5</text>
<text x="201.3" y="45.7">GND</text>
<text x="204" y="42.2">GND</text>
<text x="208.3" y="42.2">DRV_LO</text>
<text x="224.9" y="42.2">D2_1</text>
<text x="224.9" y="43.4">D2_2</text>
<text x="230.9" y="42.2">D2_3</text>
<text x="230.9" y="43.4">D2_4</text>
<text x="230.9" y="44.7">D2_5</text>
<text x="14.3" y="53.2">SW1</text>
<text x="22.5" y="48.6">+3.3V</text>
<text x="28.7" y="48.5">10k</text>
<text x="32" y="49.9">C7</text>
<text x="32.1" y="51">2.2u</text>
<text x="34.2" y="48.5">VCAP_1</text>
<text x="47.2" y="48.5">PA4</text>
<text x="47.2" y="49.8">PA5</text>
<text x="47.2" y="51">PA6</text>
<text x="47.2" y="52.3">PA7</text>
<text x="47.2" y="53.6">PA8</text>
<text x="100.3" y="51.9">74HC02</text>
<text x="100.8" y="50.8">U25A</text>
<text x="121.9" y="50.1">+3.3V</text>
<text x="124.5" y="53.7">C60</text>
<text x="128.6" y="50.1">+3.3V</text>
<text x="146.7" y="51.4">C21</text>
<text x="146.8" y="52.6">0.1u</text>
<text x="153.3" y="53.9">NCP5104</text>
<text x="154.7" y="52.8">U8</text>
<text x="199.4" y="51.4">C33</text>
<text x="199.5" y="52.6">0.1u</text>
<text x="206" y="53.9">NCP5104</text>
<text x="207.1" y="52.8">U14</text>
<text x="14.4" y="54.3">RST</text>
<text x="14.4" y="58.6">0.1u</text>
<text x="14.7" y="57.4">C2</text>
<text x="29.6" y="54.5">GND</text>
<text x="34.2" y="57.4">PH0</text>
<text x="34.2" y="58.7">PH1</text>
<text x="46.7" y="56.1">PA10</text>
<text x="46.7" y="57.4">PA11</text>
<text x="46.7" y="58.7">PA12</text>
<text x="46.7" y="59.9">PA13</text>
<text x="47.2" y="54.9">PA9</text>
<text x="92.4" y="60">74HCT04</text>
<text x="93.2" y="58.8">U23D</text>
<text x="100.3" y="58.6">74HC02</text>
<text x="100.8" y="57.4">U25B</text>
<text x="122" y="58.4">GND</text>
<text x="124.5" y="54.8">0.1u</text>
<text x="129.9" y="56.9" transform="rotate(-90 129.9 56.9)">VCC</text>
<text x="132.6" y="58.1">U25E</text>
<text x="132.7" y="59.3">74HC02</text>
<text x="143" y="59.8">10k</text>
<text x="144.2" y="56.1">GND</text>
<text x="151.3" y="56.1">Vcc</text>
<text x="151.3" y="58.7">IN</text>
<text x="155.5" y="58.7">DRV_HO</text>
<text x="156" y="56.1">VBOOT</text>
<text x="163.9" y="59.3">4.7u</text>
<text x="166.5" y="59.9">R27</text>
<text x="166.5" y="57.3">R26</text>
<text x="171.9" y="55.2">NVMFD5C446NLT1G</text>
<text x="172.1" y="58.7">S1</text>
<text x="172.1" y="59.9">G1</text>
<text x="175.6" y="54.1">Q3</text>
<text x="178.2" y="57.4">D1_1</text>
<text x="178.2" y="58.7">D1_2</text>
<text x="178.2" y="59.9">D1_3</text>
<text x="195.7" y="59.8">10k</text>
<text x="196.9" y="56.1">GND</text>
<text x="204" y="56.1">Vcc</text>
<text x="204" y="58.7">IN</text>
<text x="208.2" y="58.7">DRV_HO</text>
<text x="208.7" y="56.1">VBOOT</text>
<text x="216.6" y="59.3">4.7u</text>
<text x="219.2" y="59.9">R45</text>
<text x="219.2" y="57.3">R44</text>
<text x="224.6" y="55.2">NVMFD5C446NLT1G</text>
<text x="224.9" y="58.7">S1</text>
<text x="224.9" y="59.9">G1</text>
<text x="228.3" y="54.1">Q9</text>
<text x="230.9" y="57.4">D1_1</text>
<text x="230.9" y="58.7">D1_2</text>
<text x="230.9" y="59.9">D1_3</text>
<text x="16.9" y="62.8">GND</text>
<text x="34.2" y="63.7">PC0</text>
<text x="34.2" y="65">PC1</text>
<text x="34.2" y="61.2">PD2</text>
<text x="46.7" y="61.2">PA14</text>
<text x="46.7" y="62.5">PA15</text>
<text x="47.2" y="65">PB0</text>
<text x="100.3" y="65.2">74HC02</text>
<text x="100.8" y="64.1">U25C</text>
<text x="129.9" y="61.7" transform="rotate(-90 129.9 61.7)">GND</text>
<text x="151.3" y="61.2">SD</text>
<text x="151.3" y="63.7">GND</text>
<text x="155.6" y="63.7">DRV_LO</text>
<text x="155.8" y="61.2">BRIDGE</text>
<text x="166.8" y="61">10</text>
<text x="172.1" y="61.2">S2</text>
<text x="172.1" y="62.5">G2</text>
<text x="172.1" y="63.7">D2_1</text>
<text x="172.1" y="65">D2_2</text>
<text x="178.2" y="61.2">D1_4</text>
<text x="178.2" y="63.7">D2_3</text>
<text x="178.2" y="65">D2_4</text>
<text x="178.2" y="62.5">D1_5</text>
<text x="204" y="61.2">SD</text>
<text x="204" y="63.7">GND</text>
<text x="208.3" y="63.7">DRV_LO</text>
<text x="208.5" y="61.2">BRIDGE</text>
<text x="219.5" y="61">10</text>
<text x="224.9" y="61.2">S2</text>
<text x="224.9" y="62.5">G2</text>
<text x="224.9" y="63.7">D2_1</text>
<text x="224.9" y="65">D2_2</text>
<text x="230.9" y="61.2">D1_4</text>
<text x="230.9" y="63.7">D2_3</text>
<text x="230.9" y="65">D2_4</text>
<text x="230.9" y="62.5">D1_5</text>
<text x="34.2" y="66.3">PC2</text>
<text x="34.2" y="67.6">PC3</text>
<text x="34.2" y="68.8">PC4</text>
<text x="34.2" y="70.1">PC5</text>
<text x="34.2" y="71.4">PC6</text>
<text x="47.2" y="66.3">PB1</text>
<text x="47.2" y="67.6">PB2</text>
<text x="47.2" y="68.8">PB3</text>
<text x="47.2" y="70.1">PB4</text>
<text x="47.2" y="71.4">PB5</text>
<text x="121.9" y="69.5">+3.3V</text>
<text x="128.6" y="69.5">+3.3V</text>
<text x="128.6" y="67.2">GND</text>
<text x="146.7" y="69.5">C22</text>
<text x="146.8" y="70.7">0.1u</text>
<text x="148.6" y="67.2">GND</text>
<text x="154.7" y="70.9">U9</text>
<text x="178.2" y="66.3">D2_5</text>
<text x="199.4" y="69.5">C34</text>
<text x="199.5" y="70.7">0.1u</text>
<text x="201.3" y="67.2">GND</text>
<text x="207.1" y="70.9">U15</text>
<text x="230.9" y="66.3">D2_5</text>
<text x="263.2" y="66.7">C43</text>
<text x="263.3" y="67.8">470u</text>
<text x="268.3" y="66.7">C47</text>
<text x="268.4" y="67.8">470u</text>
<text x="273.1" y="66.7">C48</text>
<text x="273.1" y="67.8">4.7u</text>
<text x="275" y="71.4">GND</text>
<text x="277.5" y="66.7">C49</text>
<text x="277.6" y="67.8">4.7u</text>
<text x="34.2" y="76.4">PC10</text>
<text x="34.2" y="77.7">PC11</text>
<text x="34.2" y="72.6">PC7</text>
<text x="34.2" y="73.9">PC8</text>
<text x="34.2" y="75.2">PC9</text>
<text x="46.7" y="77.7">PB10</text>
<text x="47.2" y="72.6">PB6</text>
<text x="47.2" y="73.9">PB7</text>
<text x="47.2" y="75.2">PB8</text>
<text x="47.2" y="76.4">PB9</text>
<text x="92.4" y="74.6">74HCT04</text>
<text x="93.2" y="73.4">U23E</text>
<text x="100.3" y="73.2">74HC02</text>
<text x="100.8" y="72">U26D</text>
<text x="122" y="77.7">GND</text>
<text x="124.5" y="73">C61</text>
<text x="124.5" y="74.2">0.1u</text>
<text x="129.9" y="76.3" transform="rotate(-90 129.9 76.3)">VCC</text>
<text x="132.6" y="77.5">U26E</text>
<text x="143" y="77.9">10k</text>
<text x="144.2" y="74.2">GND</text>
<text x="151.3" y="74.2">Vcc</text>
<text x="151.3" y="76.8">IN</text>
<text x="153.3" y="72">NCP5104</text>
<text x="155.5" y="76.8">DRV_HO</text>
<text x="156" y="74.2">VBOOT</text>
<text x="163.9" y="77.4">4.7u</text>
<text x="166.5" y="75.4">R28</text>
<text x="166.5" y="78">R29</text>
<text x="171.9" y="73.3">NVMFD5C446NLT1G</text>
<text x="172.1" y="76.8">S1</text>
<text x="175.6" y="72.2">Q4</text>
<text x="178.2" y="75.5">D1_1</text>
<text x="178.2" y="76.8">D1_2</text>
<text x="195.7" y="77.9">10k</text>
<text x="196.9" y="74.2">GND</text>
<text x="204" y="74.2">Vcc</text>
<text x="204" y="76.8">IN</text>
<text x="206" y="72">NCP5104</text>
<text x="208.2" y="76.8">DRV_HO</text>
<text x="208.7" y="74.2">VBOOT</text>
<text x="216.6" y="77.4">4.7u</text>
<text x="219.2" y="75.4">R46</text>
<text x="219.2" y="78">R47</text>
<text x="224.6" y="73.3">NVMFD5C446NLT1G</text>
<text x="224.9" y="76.8">S1</text>
<text x="228.1" y="72.2">Q10</text>
<text x="230.9" y="75.5">D1_1</text>
<text x="230.9" y="76.8">D1_2</text>
<text x="261.9" y="77.1">+BATT</text>
<text x="265.5" y="73.3">+BATT</text>
<text x="267.9" y="77.9">J14</text>
<text x="269.3" y="73.3">PWR_FLAG</text>
<text x="34.2" y="79">PC12</text>
<text x="34.2" y="80.3">PC13</text>
<text x="34.2" y="81.5">PC14</text>
<text x="34.2" y="82.8">PC15</text>
<text x="39.4" y="83.5" transform="rotate(-90 39.4 83.5)">VSS</text>
<text x="40.6" y="83.5" transform="rotate(-90 40.6 83.5)">VSS</text>
<text x="41.9" y="83.5" transform="rotate(-90 41.9 83.5)">VSS</text>
<text x="43.2" y="83.5" transform="rotate(-90 43.2 83.5)">VSS</text>
<text x="44.4" y="83.5" transform="rotate(-90 44.4 83.5)">VSSA</text>
<text x="46.7" y="79">PB12</text>
<text x="46.7" y="80.3">PB13</text>
<text x="46.7" y="81.5">PB14</text>
<text x="46.7" y="82.8">PB15</text>
<text x="100.3" y="79.9">74HC02</text>
<text x="100.8" y="78.7">U26A</text>
<text x="129.9" y="81" transform="rotate(-90 129.9 81)">GND</text>
<text x="132.7" y="78.6">74HC02</text>
<text x="151.3" y="79.3">SD</text>
<text x="151.3" y="81.8">GND</text>
<text x="155.6" y="81.8">DRV_LO</text>
<text x="155.8" y="79.3">BRIDGE</text>
<text x="166.8" y="79.1">10</text>
<text x="172.1" y="78">G1</text>
<text x="172.1" y="79.3">S2</text>
<text x="172.1" y="80.6">G2</text>
<text x="172.1" y="81.8">D2_1</text>
<text x="172.1" y="83.1">D2_2</text>
<text x="178.2" y="79.3">D1_4</text>
<text x="178.2" y="81.8">D2_3</text>
<text x="178.2" y="83.1">D2_4</text>
<text x="178.2" y="78">D1_3</text>
<text x="178.2" y="80.6">D1_5</text>
<text x="204" y="79.3">SD</text>
<text x="204" y="81.8">GND</text>
<text x="208.3" y="81.8">DRV_LO</text>
<text x="208.5" y="79.3">BRIDGE</text>
<text x="219.5" y="79.1">10</text>
<text x="224.9" y="78">G1</text>
<text x="224.9" y="79.3">S2</text>
<text x="224.9" y="80.6">G2</text>
<text x="224.9" y="81.8">D2_1</text>
<text x="224.9" y="83.1">D2_2</text>
<text x="230.9" y="79.3">D1_4</text>
<text x="230.9" y="81.8">D2_3</text>
<text x="230.9" y="83.1">D2_4</text>
<text x="230.9" y="78">D1_3</text>
<text x="230.9" y="80.6">D1_5</text>
<text x="266.4" y="81.2">2</text>
<text x="266.4" y="82.5">4</text>
<text x="267.2" y="79">3522-2</text>
<text x="270.3" y="81.2">1</text>
<text x="270.3" y="82.5">3</text>
<text x="43.2" y="87.6">GND</text>
<text x="92.4" y="87.9">74HCT04</text>
<text x="93.2" y="86.7">U23F</text>
<text x="100.3" y="86.5">74HC02</text>
<text x="100.8" y="85.4">U26B</text>
<text x="128.6" y="86.6">GND</text>
<text x="148.6" y="85.3">GND</text>
<text x="178.2" y="84.4">D2_5</text>
<text x="201.3" y="85.3">GND</text>
<text x="230.9" y="84.4">D2_5</text>
<text x="259.1" y="87.6">PWR_FLAG</text>
<text x="266.6" y="88.5">N.C</text>
<text x="266.6" y="89.8">N.O</text>
<text x="100.3" y="93.2">74HC02</text>
<text x="100.8" y="92">U26C</text>
<text x="144.2" y="95.8">GND</text>
<text x="146.7" y="91.1">C23</text>
<text x="146.8" y="92.3">0.1u</text>
<text x="151.3" y="95.8">Vcc</text>
<text x="153.3" y="93.6">NCP5104</text>
<text x="154.4" y="92.5">U10</text>
<text x="156" y="95.8">VBOOT</text>
<text x="171.9" y="94.9">NVMFD5C446NLT1G</text>
<text x="175.6" y="93.7">Q5</text>
<text x="196.9" y="95.8">GND</text>
<text x="199.4" y="91.1">C35</text>
<text x="199.5" y="92.3">0.1u</text>
<text x="204" y="95.8">Vcc</text>
<text x="206" y="93.6">NCP5104</text>
<text x="207.1" y="92.5">U16</text>
<text x="208.7" y="95.8">VBOOT</text>
<text x="224.6" y="94.9">NVMFD5C446NLT1G</text>
<text x="228.1" y="93.7">Q11</text>
<text x="255.6" y="95.4">SW4</text>
<text x="27.1" y="100.9">ADC</text>
<text x="27.5" y="99.8">J2</text>
<text x="33.3" y="100.3">+3.3V</text>
<text x="35.4" y="100.9">ADC_Vdd</text>
<text x="37" y="99.8">J3</text>
<text x="55" y="100.3">+5V</text>
<text x="61" y="101.6">+5V0.1u</text>
<text x="62.7" y="100.6">C15</text>
<text x="143" y="99.5">10k</text>
<text x="151.3" y="98.4">IN</text>
<text x="151.3" y="100.9">SD</text>
<text x="155.5" y="98.4">DRV_HO</text>
<text x="155.8" y="100.9">BRIDGE</text>
<text x="163.9" y="99">4.7u</text>
<text x="166.5" y="97">R30</text>
<text x="166.5" y="99.6">R31</text>
<text x="166.8" y="100.7">10</text>
<text x="172.1" y="98.4">S1</text>
<text x="172.1" y="99.6">G1</text>
<text x="172.1" y="100.9">S2</text>
<text x="178.2" y="100.9">D1_4</text>
<text x="178.2" y="97.1">D1_1</text>
<text x="178.2" y="98.4">D1_2</text>
<text x="178.2" y="99.6">D1_3</text>
<text x="195.7" y="99.5">10k</text>
<text x="204" y="98.4">IN</text>
<text x="204" y="100.9">SD</text>
<text x="208.2" y="98.4">DRV_HO</text>
<text x="208.5" y="100.9">BRIDGE</text>
<text x="216.6" y="99">4.7u</text>
<text x="219.2" y="97">R48</text>
<text x="219.2" y="99.6">R49</text>
<text x="219.5" y="100.7">10</text>
<text x="224.9" y="98.4">S1</text>
<text x="224.9" y="99.6">G1</text>
<text x="224.9" y="100.9">S2</text>
<text x="230.9" y="100.9">D1_4</text>
<text x="230.9" y="97.1">D1_1</text>
<text x="230.9" y="98.4">D1_2</text>
<text x="230.9" y="99.6">D1_3</text>
<text x="255.5" y="96.6">EMG</text>
<text x="260.4" y="96.2">R52</text>
<text x="260.5" y="97.4">10k</text>
<text x="264.9" y="99.6">FET_P</text>
<text x="265" y="98.4">Q15</text>
<text x="273.5" y="101.8">FET_N</text>
<text x="273.6" y="100.7">Q14</text>
<text x="278.4" y="101.9">JP2</text>
<text x="56.6" y="106.3">1k</text>
<text x="56.6" y="105.1">R12</text>
<text x="59.7" y="105">1k</text>
<text x="59.8" y="103.8">R13</text>
<text x="63.9" y="107.6">R15</text>
<text x="64.8" y="106">GND3</text>
<text x="69.6" y="106.3">ENC</text>
<text x="69.7" y="105.2">J5</text>
<text x="148.6" y="106.9">GND</text>
<text x="151.3" y="103.4">GND</text>
<text x="155.6" y="103.4">DRV_LO</text>
<text x="172.1" y="102.2">G2</text>
<text x="172.1" y="103.4">D2_1</text>
<text x="172.1" y="104.7">D2_2</text>
<text x="178.2" y="103.4">D2_3</text>
<text x="178.2" y="104.7">D2_4</text>
<text x="178.2" y="106">D2_5</text>
<text x="178.2" y="102.2">D1_5</text>
<text x="201.3" y="106.9">GND</text>
<text x="204" y="103.4">GND</text>
<text x="208.3" y="103.4">DRV_LO</text>
<text x="224.9" y="102.2">G2</text>
<text x="224.9" y="103.4">D2_1</text>
<text x="224.9" y="104.7">D2_2</text>
<text x="230.9" y="103.4">D2_3</text>
<text x="230.9" y="104.7">D2_4</text>
<text x="230.9" y="106">D2_5</text>
<text x="230.9" y="102.2">D1_5</text>
<text x="253.1" y="102.5">GND</text>
<text x="269.3" y="102.6">R58</text>
<text x="269.3" y="103.7">10k</text>
<text x="278.4" y="103">Relay_JP</text>
<text x="60.4" y="108.9">R14</text>
<text x="60.4" y="113.4">R59</text>
<text x="60.5" y="110.1">4.7k</text>
<text x="63.9" y="112.1">R60</text>
<text x="63.9" y="113.2">10k</text>
<text x="63.9" y="108.8">4.7k</text>
<text x="144.2" y="113.9">GND</text>
<text x="146.7" y="109.2">C24</text>
<text x="146.8" y="110.4">0.1u</text>
<text x="151.3" y="113.9">Vcc</text>
<text x="153.3" y="111.7">NCP5104</text>
<text x="154.4" y="110.6">U11</text>
<text x="156" y="113.9">VBOOT</text>
<text x="171.9" y="113">NVMFD5C446NLT1G</text>
<text x="175.6" y="111.8">Q6</text>
<text x="196.9" y="113.9">GND</text>
<text x="199.4" y="109.2">C36</text>
<text x="199.5" y="110.4">0.1u</text>
<text x="204" y="113.9">Vcc</text>
<text x="206" y="111.7">NCP5104</text>
<text x="207.1" y="110.6">U17</text>
<text x="208.7" y="113.9">VBOOT</text>
<text x="224.6" y="113">NVMFD5C446NLT1G</text>
<text x="228.1" y="111.8">Q12</text>
<text x="267.6" y="113.5">D22</text>
<text x="276.3" y="108.5">GND</text>
<text x="39.7" y="116.1">GND</text>
<text x="58.5" y="118">GND</text>
<text x="60.4" y="114.5">10k</text>
<text x="62" y="116.8">GND</text>
<text x="143" y="117.6">10k</text>
<text x="151.3" y="116.5">IN</text>
<text x="151.3" y="119">SD</text>
<text x="155.5" y="116.5">DRV_HO</text>
<text x="155.8" y="119">BRIDGE</text>
<text x="163.9" y="117.1">4.7u</text>
<text x="166.5" y="115.1">R32</text>
<text x="166.5" y="117.7">R33</text>
<text x="166.8" y="118.8">10</text>
<text x="172.1" y="116.5">S1</text>
<text x="172.1" y="117.7">G1</text>
<text x="172.1" y="119">S2</text>
<text x="178.2" y="119">D1_4</text>
<text x="178.2" y="115.2">D1_1</text>
<text x="178.2" y="116.5">D1_2</text>
<text x="178.2" y="117.7">D1_3</text>
<text x="195.7" y="117.6">10k</text>
<text x="204" y="116.5">IN</text>
<text x="204" y="119">SD</text>
<text x="208.2" y="116.5">DRV_HO</text>
<text x="208.5" y="119">BRIDGE</text>
<text x="216.6" y="117.1">4.7u</text>
<text x="219.2" y="117.7">R51</text>
<text x="219.2" y="115.1">R50</text>
<text x="219.5" y="118.8">10</text>
<text x="224.9" y="116.5">S1</text>
<text x="224.9" y="117.7">G1</text>
<text x="224.9" y="119">S2</text>
<text x="230.9" y="119">D1_4</text>
<text x="230.9" y="115.2">D1_1</text>
<text x="230.9" y="116.5">D1_2</text>
<text x="230.9" y="117.7">D1_3</text>
<text x="261.3" y="114.6">+BATT</text>
<text x="263.6" y="115.3">2.2k</text>
<text x="263.6" y="119.8">2.2k</text>
<text x="263.7" y="114.2">R53</text>
<text x="263.7" y="118.6">R54</text>
<text x="265.8" y="119.1">MAIN_BATT</text>
<text x="267.2" y="114.6">BATT</text>
<text x="267.6" y="117.9">D23</text>
<text x="32.8" y="126">C55</text>
<text x="64.4" y="124.8">+3.3V</text>
<text x="148.6" y="125">GND</text>
<text x="151.3" y="121.5">GND</text>
<text x="155.6" y="121.5">DRV_LO</text>
<text x="172.1" y="120.3">G2</text>
<text x="172.1" y="121.5">D2_1</text>
<text x="172.1" y="122.8">D2_2</text>
<text x="178.2" y="121.5">D2_3</text>
<text x="178.2" y="122.8">D2_4</text>
<text x="178.2" y="124.1">D2_5</text>
<text x="178.2" y="120.3">D1_5</text>
<text x="201.3" y="125">GND</text>
<text x="204" y="121.5">GND</text>
<text x="208.3" y="121.5">DRV_LO</text>
<text x="224.9" y="120.3">G2</text>
<text x="224.9" y="121.5">D2_1</text>
<text x="224.9" y="122.8">D2_2</text>
<text x="230.9" y="121.5">D2_3</text>
<text x="230.9" y="122.8">D2_4</text>
<text x="230.9" y="124.1">D2_5</text>
<text x="230.9" y="120.3">D1_5</text>
<text x="263.6" y="124.2">2.2k</text>
<text x="263.7" y="123.1">R55</text>
<text x="265.3" y="123.5">MOTOR_BATT</text>
<text x="267.6" y="122.4">D24</text>
<text x="23.8" y="127">+3.3V</text>
<text x="32.2" y="131.1">C54</text>
<text x="32.8" y="127.2">C56</text>
<text x="33.1" y="127.1">1u</text>
<text x="33.1" y="128.4">1u</text>
<text x="38.6" y="127.9">V0</text>
<text x="38.6" y="129.2">VOUT</text>
<text x="38.6" y="130.4">CAP1N</text>
<text x="38.6" y="131.7">CAP1P</text>
<text x="59.2" y="128.1">R66</text>
<text x="59.5" y="129.3">10</text>
<text x="67" y="131.3">NPN</text>
<text x="67" y="130.2">Q16</text>
<text x="70.5" y="127">LS1</text>
<text x="70.6" y="128.2">Speaker</text>
<text x="263.7" y="131.9">R56</text>
<text x="263.7" y="127.5">R70</text>
<text x="263.7" y="128.7">510</text>
<text x="266.5" y="128">5V_dcdc</text>
<text x="267.6" y="131.3">D25</text>
<text x="267.6" y="126.8">D31</text>
<text x="25.8" y="134.3">R68</text>
<text x="25.8" y="135.5">10k</text>
<text x="29.3" y="133">R69</text>
<text x="29.3" y="134.2">10k</text>
<text x="32.1" y="132.2">0.1u</text>
<text x="38.6" y="133">VDD</text>
<text x="38.6" y="134.2">VSS</text>
<text x="38.6" y="135.5">SDA</text>
<text x="38.6" y="136.8">SCL</text>
<text x="45" y="132.4">U22</text>
<text x="45" y="133.6">AQM0802</text>
<text x="66.8" y="132.4">R67</text>
<text x="66.9" y="133.3">120</text>
<text x="68.6" y="135.5">GND</text>
<text x="154.9" y="134">+3.3V</text>
<text x="157.5" y="137.5">C3</text>
<text x="159.4" y="136.5">+3.3V</text>
<text x="161.7" y="137">R5</text>
<text x="161.7" y="138">R6</text>
<text x="165.6" y="137.3">D3</text>
<text x="165.6" y="136.4">D2</text>
<text x="186.8" y="135.5">SERIAL0</text>
<text x="187.5" y="137.7">VBUS</text>
<text x="188.2" y="134.4">J4</text>
<text x="196.2" y="135.6">+5V</text>
<text x="202.9" y="136.2">+5V0.1u</text>
<text x="204.6" y="135.2">C53</text>
<text x="232.2" y="134.8">0.1u</text>
<text x="232.2" y="133.6">C57</text>
<text x="238.6" y="137.5">J9</text>
<text x="261.6" y="136.8">+3.3V</text>
<text x="262" y="132.4">+5V</text>
<text x="263.7" y="136.4">R57</text>
<text x="263.7" y="133.1">510</text>
<text x="263.7" y="137.5">330</text>
<text x="267.5" y="136.9">3.3V</text>
<text x="267.6" y="135.7">D26</text>
<text x="267.8" y="132.4">5V</text>
<text x="38.6" y="138">/RST</text>
<text x="155" y="142.2">GND</text>
<text x="157.6" y="138.6">0.1u</text>
<text x="161.5" y="139.1">330</text>
<text x="161.7" y="141.8">R7</text>
<text x="165.3" y="138.5">LED</text>
<text x="165.5" y="138.9">R9</text>
<text x="165.6" y="141.1">D4</text>
<text x="171" y="138.7">Vdd</text>
<text x="171" y="139.6">GP0</text>
<text x="171" y="140.6">GP1</text>
<text x="171" y="141.5">nRST</text>
<text x="171" y="142.5">URx</text>
<text x="171" y="143.4">UTx</text>
<text x="174.2" y="141.5">Vusb</text>
<text x="174.5" y="143.4">SDA</text>
<text x="174.6" y="142.5">SCL</text>
<text x="174.8" y="138.7">Vss</text>
<text x="175.2" y="139.6">D+</text>
<text x="183.2" y="140.9">GND</text>
<text x="187" y="143.3" transform="rotate(-90 187 143.3)">Shield</text>
<text x="188.3" y="143.3" transform="rotate(-90 188.3 143.3)">GND</text>
<text x="188.8" y="140.3">D+</text>
<text x="189.1" y="142.8">ID</text>
<text x="211.6" y="140.9">SERIAL1</text>
<text x="211.7" y="139.8">J16</text>
<text x="234" y="139">GND3</text>
<text x="238.5" y="138.7">SERVO</text>
<text x="269.3" y="141.2">GND</text>
<text x="58.8" y="149.5">GND</text>
<text x="62.7" y="145.3">2</text>
<text x="62.7" y="147.3">C</text>
<text x="62.7" y="149.2">1</text>
<text x="67.4" y="147.3">C</text>
<text x="67.6" y="149.2">4</text>
<text x="67.6" y="145.3">8</text>
<text x="70.2" y="149.5">GND</text>
<text x="171" y="144.4">GP2</text>
<text x="174.6" y="144.4">GP3</text>
<text x="187" y="147.6">GND</text>
<text x="252.3" y="153.3">MOTOR0</text>
<text x="255.1" y="152.1">J6</text>
<text x="262.6" y="152.1">C44</text>
<text x="262.6" y="153.2">0.1u</text>
<text x="266.3" y="153.3">MOTOR1</text>
<text x="268.5" y="152.1">J10</text>
<text x="276.6" y="152.1">C50</text>
<text x="276.6" y="153.2">0.1u</text>
<text x="93.6" y="159">+3.3V</text>
<text x="98.1" y="159">+3.3V</text>
<text x="111.6" y="159.3">R10</text>
<text x="111.6" y="160.5">R11</text>
<text x="111.6" y="161.8">R71</text>
<text x="117.3" y="161.9">blue_A</text>
<text x="122.3" y="161.9">blue_K</text>
<text x="158.2" y="161.7">FILTER</text>
<text x="158.9" y="160.5">R61</text>
<text x="158.9" y="161.8">R62</text>
<text x="164" y="161.9">DAT2</text>
<text x="170.6" y="157.7">microSD</text>
<text x="171.7" y="156.6">J15</text>
<text x="252.3" y="159.6">MOTOR2</text>
<text x="255.1" y="158.5">J7</text>
<text x="262.6" y="158.4">C45</text>
<text x="262.6" y="159.6">0.1u</text>
<text x="266.3" y="159.6">MOTOR3</text>
<text x="268.5" y="158.5">J11</text>
<text x="276.6" y="158.4">C51</text>
<text x="276.6" y="159.6">0.1u</text>
<text x="95.3" y="167.6">SW2</text>
<text x="95.6" y="162.6">R2</text>
<text x="95.7" y="163.7">10k</text>
<text x="99.7" y="167.6">SW3</text>
<text x="100.1" y="162.6">R3</text>
<text x="100.1" y="163.7">10k</text>
<text x="111.7" y="162.9">330</text>
<text x="117.3" y="163.1">green_A</text>
<text x="117.3" y="164.4">red_A</text>
<text x="121.7" y="163.1">green_K</text>
<text x="122.7" y="164.4">red_K</text>
<text x="127.4" y="166.6">GND</text>
<text x="158.2" y="162.9">FILTER</text>
<text x="158.2" y="165.5">FILTER</text>
<text x="158.9" y="164.3">R63</text>
<text x="158.9" y="166.9">R64</text>
<text x="160.6" y="163.5">+3.3V</text>
<text x="164" y="163.1">DAT3/CD</text>
<text x="164" y="164.4">CMD</text>
<text x="164" y="165.7">VDD</text>
<text x="164" y="166.9">CLK</text>
<text x="252.3" y="166">MOTOR4</text>
<text x="255.1" y="164.8">J8</text>
<text x="262.6" y="164.8">C46</text>
<text x="262.6" y="165.9">0.1u</text>
<text x="266.3" y="166">MOTOR5</text>
<text x="268.5" y="164.8">J12</text>
<text x="276.6" y="164.8">C52</text>
<text x="276.6" y="165.9">0.1u</text>
<text x="93.7" y="173">GND</text>
<text x="95.3" y="168.7">SW0</text>
<text x="98.1" y="173">GND</text>
<text x="99.7" y="168.7">SW1</text>
<text x="158.2" y="168">FILTER</text>
<text x="164" y="172">DET_A</text>
<text x="164" y="168.2">VSS</text>
<text x="164" y="169.5">DAT0</text>
<text x="164" y="170.7">DAT1</text>
<text x="164" y="173.3">DET_B</text>
<text x="177.5" y="173.3">SHIELD</text>
<text x="271.3" y="173.1">J17</text>
<text x="260.9" y="177.1">+BATT</text>
<text x="271.1" y="179.3">TO_VOLTMETER</text>
<text x="271.1" y="174.3">VOLTMETER</text>
<text x="271.3" y="178.2">J18</text>
<text x="260.1" y="180.3">GND</text>
</g>
<g font-size=".9">
<text x="143.4" y="10">Batt</text>
<text x="196.1" y="10">Batt</text>
<text x="27.2" y="15.5">22uH FB</text>
<text x="28.3" y="17.6">Batt</text>
<text x="140.5" y="17.3">Batt</text>
<text x="147.8" y="16">Batt 1</text>
<text x="155.4" y="12.2">Batt</text>
<text x="183.2" y="17.3">MOTOR_BATT</text>
<text x="192.9" y="17.3">Batt</text>
<text x="200.5" y="16">Batt 1</text>
<text x="208.2" y="12.2">Batt</text>
<text x="235.9" y="17.3">MOTOR_BATT</text>
<text x="16.8" y="22.7">FB</text>
<text x="83.6" y="21.1">Motor0_PWM</text>
<text x="84.3" y="18.5">Motor0_CW</text>
<text x="104.3" y="19.8">13 Motor0_L_PWM</text>
<text x="142.9" y="18.5">Motor0_L_PWM</text>
<text x="143.3" y="19">R16</text>
<text x="163.8" y="18.4">C25Motor0_L</text>
<text x="165.3" y="23.6">Motor0_L</text>
<text x="166.8" y="18.8">10</text>
<text x="168.3" y="23.7">GND5</text>
<text x="185.1" y="23.6">Motor0_L</text>
<text x="195.6" y="18.5">Motor1_L_PWM</text>
<text x="195.7" y="19">R34</text>
<text x="216.5" y="18.4">C37Motor1_L</text>
<text x="218" y="23.6">Motor1_L</text>
<text x="219.5" y="18.8">10</text>
<text x="221" y="23.7">GND5</text>
<text x="237.8" y="23.6">Motor1_L</text>
<text x="105.7" y="26.5">Motor0_R_PWM</text>
<text x="143.4" y="28.1">Batt</text>
<text x="196.1" y="28.1">Batt</text>
<text x="10" y="33.1">OSC_IN</text>
<text x="19" y="33.1">OSC_OUT</text>
<text x="83.6" y="34.4">Motor1_PWM</text>
<text x="84.3" y="31.9">Motor1_CW</text>
<text x="105.7" y="33.1">Motor1_L_PWM</text>
<text x="140.2" y="35.4">Batt</text>
<text x="147.8" y="34.1">Batt 1</text>
<text x="155.4" y="30.3">Batt</text>
<text x="183.2" y="35.4">MOTOR_BATT</text>
<text x="192.9" y="35.4">Batt</text>
<text x="200.5" y="34.1">Batt 1</text>
<text x="208.2" y="30.3">Batt</text>
<text x="235.9" y="35.4">MOTOR_BATT</text>
<text x="104.3" y="39.8">10 Motor1_R_PWM</text>
<text x="142.8" y="36.6">Motor0_R_PWM 2</text>
<text x="143" y="37.1">R17</text>
<text x="163.8" y="36.5">C26Motor0_R</text>
<text x="165.2" y="41.7">Motor0_R</text>
<text x="166.8" y="36.9">10</text>
<text x="168.3" y="41.8">GND5</text>
<text x="185.1" y="41.7">Motor0_R</text>
<text x="195.5" y="36.6">Motor1_R_PWM 2</text>
<text x="195.7" y="37.1">R35</text>
<text x="216.5" y="36.5">C38Motor1_R</text>
<text x="217.9" y="41.7">Motor1_R</text>
<text x="219.5" y="36.9">10</text>
<text x="221" y="41.8">GND5</text>
<text x="237.8" y="41.7">Motor1_R</text>
<text x="10.9" y="46.5">3GND SWCLK</text>
<text x="13.7" y="47.7">SWDIO</text>
<text x="30.9" y="43">RST 7</text>
<text x="49.4" y="43">14ADC4</text>
<text x="49.4" y="44.3">15Buzzer_PWM</text>
<text x="49.4" y="45.5">16USART2_TX</text>
<text x="49.4" y="46.8">17USART2_RX</text>
<text x="84.3" y="46.5">Motor2_CW</text>
<text x="104.3" y="47.7">13 Motor2_L_PWM</text>
<text x="13.7" y="49">RST</text>
<text x="49.4" y="48.1">20ADC5</text>
<text x="49.4" y="49.3">21ADC6</text>
<text x="49.4" y="50.6">22ENC_CH1</text>
<text x="49.4" y="51.9">23ENC_CH2</text>
<text x="49.4" y="53.1">41Motor4_PWM</text>
<text x="83.6" y="49">Motor2_PWM</text>
<text x="143.4" y="49.7">Batt</text>
<text x="155.4" y="51.9">Batt</text>
<text x="196.1" y="49.7">Batt</text>
<text x="208.2" y="51.9">Batt</text>
<text x="10.9" y="56.3">RST</text>
<text x="28.4" y="58.2">OSC_OUT 6</text>
<text x="29.4" y="57">OSC_IN 5</text>
<text x="49.4" y="55.7">43Motor3_PWM</text>
<text x="49.4" y="57">44Motor2_PWM</text>
<text x="49.4" y="58.2">45EMG_IO</text>
<text x="49.4" y="59.5">46SWDIO</text>
<text x="49.4" y="54.4">42Motor5_PWM</text>
<text x="84.3" y="59.8">Motor3_CW</text>
<text x="105.7" y="54.4">Motor2_R_PWM</text>
<text x="140.2" y="57">Batt</text>
<text x="142.9" y="58.2">Motor2_L_PWM</text>
<text x="143" y="58.7">R18</text>
<text x="147.8" y="55.7">Batt 1</text>
<text x="163.8" y="58.1">C27Motor2_L</text>
<text x="166.8" y="58.5">10</text>
<text x="183.2" y="57">MOTOR_BATT</text>
<text x="192.9" y="57">Batt</text>
<text x="195.6" y="58.2">Motor3_L_PWM</text>
<text x="195.7" y="58.7">R36</text>
<text x="200.5" y="55.7">Batt 1</text>
<text x="216.5" y="58.1">C39Motor3_L</text>
<text x="219.5" y="58.5">10</text>
<text x="235.9" y="57">MOTOR_BATT</text>
<text x="28.5" y="60.8">ADRESS3</text>
<text x="30.3" y="65.8">ADC2</text>
<text x="30.3" y="64.6">ADC1</text>
<text x="30.3" y="63.3">ADC0</text>
<text x="49.4" y="60.8">49SWCLK</text>
<text x="49.4" y="64.6">26ADC9</text>
<text x="49.4" y="65.8">27SW0</text>
<text x="83.6" y="62.4">Motor3_PWM</text>
<text x="105.7" y="61.1">Motor3_L_PWM</text>
<text x="165.3" y="63.3">Motor2_L</text>
<text x="168.3" y="63.4">GND5</text>
<text x="185.1" y="63.3">Motor2_L</text>
<text x="218" y="63.3">Motor3_L</text>
<text x="221" y="63.4">GND5</text>
<text x="237.8" y="63.3">Motor3_L</text>
<text x="255.5" y="64.9">MOTOR_BATT</text>
<text x="27.8" y="70.9">Motor5_CW 37</text>
<text x="30.3" y="69.7">ADC8</text>
<text x="30.3" y="67.1">ADC3</text>
<text x="30.3" y="68.4">ADC7</text>
<text x="49.4" y="67.1">28SW1</text>
<text x="49.4" y="68.4">55ADRESS2</text>
<text x="49.4" y="69.7">56ADRESS0</text>
<text x="49.4" y="70.9">57ADRESS1</text>
<text x="104.3" y="67.7">10 Motor3_R_PWM</text>
<text x="143.4" y="67.7">Batt</text>
<text x="155.4" y="70">Batt</text>
<text x="196.1" y="67.7">Batt</text>
<text x="208.2" y="70">Batt</text>
<text x="27.4" y="77.3">USART3_RX 52</text>
<text x="27.5" y="76">USART3_TX 51</text>
<text x="27.8" y="72.2">Motor4_CW 38</text>
<text x="27.8" y="73.5">Motor3_CW 39</text>
<text x="27.8" y="74.7">Motor2_CW 40</text>
<text x="49.4" y="77.3">29I2C2_SCL</text>
<text x="49.4" y="72.2">58Motor1_PWM</text>
<text x="49.4" y="73.5">59Motor0_PWM</text>
<text x="49.4" y="74.7">61Motor0_CW</text>
<text x="49.4" y="76">62Motor1_CW</text>
<text x="83.6" y="77">Motor4_PWM</text>
<text x="84.3" y="74.4">Motor4_CW</text>
<text x="104.3" y="75.7">13 Motor4_L_PWM</text>
<text x="140.2" y="75.1">Batt</text>
<text x="142.8" y="76.3">Motor2_R_PWM 2</text>
<text x="143" y="76.8">R19</text>
<text x="147.8" y="73.8">Batt 1</text>
<text x="163.8" y="76.2">C28Motor2_R</text>
<text x="166.8" y="76.6">10</text>
<text x="183.2" y="75.1">MOTOR_BATT</text>
<text x="192.9" y="75.1">Batt</text>
<text x="195.5" y="76.3">Motor3_R_PWM 2</text>
<text x="195.7" y="76.8">R37</text>
<text x="200.5" y="73.8">Batt 1</text>
<text x="216.5" y="76.2">C40Motor3_R</text>
<text x="219.5" y="76.6">10</text>
<text x="235.9" y="75.1">MOTOR_BATT</text>
<text x="272.4" y="75.1">Batt</text>
<text x="27.9" y="81.1">LED_Green 3</text>
<text x="28.5" y="78.5">I2C2_SDA 53</text>
<text x="28.5" y="82.4">LED_Blue 4</text>
<text x="28.8" y="79.8">LED_Red 2</text>
<text x="49.4" y="78.5">33SPI2_NSS</text>
<text x="49.4" y="79.8">34SPI2_SCK</text>
<text x="49.4" y="81.1">35SPI2_MISO</text>
<text x="49.4" y="82.4">36SPI2_MOSI</text>
<text x="105.7" y="82.4">Motor4_R_PWM</text>
<text x="165.2" y="81.4">Motor2_R</text>
<text x="168.3" y="81.5">GND5</text>
<text x="185.1" y="81.4">Motor2_R</text>
<text x="217.9" y="81.4">Motor3_R</text>
<text x="221" y="81.5">GND5</text>
<text x="237.8" y="81.4">Motor3_R</text>
<text x="84.3" y="87.8">Motor5_CW</text>
<text x="105.7" y="89">Motor5_L_PWM</text>
<text x="143.4" y="89.3">Batt</text>
<text x="196.1" y="89.3">Batt</text>
<text x="254.8" y="89.3">MOTOR_BATT</text>
<text x="83.6" y="90.3">Motor5_PWM</text>
<text x="104.3" y="95.7">10 Motor5_R_PWM</text>
<text x="147.8" y="95.4">Batt 1</text>
<text x="155.4" y="91.6">Batt</text>
<text x="200.5" y="95.4">Batt 1</text>
<text x="208.2" y="91.6">Batt</text>
<text x="251.7" y="94.1">Batt</text>
<text x="140.2" y="96.6">Batt</text>
<text x="142.9" y="97.9">Motor4_L_PWM</text>
<text x="143" y="98.4">R20</text>
<text x="163.8" y="97.8">C29Motor4_L</text>
<text x="166.8" y="98.2">10</text>
<text x="183.2" y="96.6">MOTOR_BATT</text>
<text x="192.9" y="96.6">Batt</text>
<text x="195.6" y="97.9">Motor5_L_PWM</text>
<text x="195.7" y="98.4">R38</text>
<text x="216.5" y="97.8">C41Motor5_L</text>
<text x="219.5" y="98.2">10</text>
<text x="235.9" y="96.6">MOTOR_BATT</text>
<text x="261.2" y="101.1">Batt</text>
<text x="264.2" y="100.8">EMG_IO</text>
<text x="264.3" y="100.8" transform="rotate(-90 264.3 100.8)">2</text>
<text x="29.5" y="107.1">ADC4</text>
<text x="29.5" y="105.8">ADC3</text>
<text x="29.5" y="104.6">ADC2</text>
<text x="29.5" y="103.3">ADC1</text>
<text x="29.5" y="102">ADC0</text>
<text x="143.4" y="107.4">Batt</text>
<text x="165.3" y="103">Motor4_L</text>
<text x="168.3" y="103.1">GND5</text>
<text x="185.1" y="103">Motor4_L</text>
<text x="196.1" y="107.4">Batt</text>
<text x="218" y="103">Motor5_L</text>
<text x="221" y="103.1">GND5</text>
<text x="237.8" y="103">Motor5_L</text>
<text x="28.1" y="113.5">10 ADC9</text>
<text x="29.5" y="112.2">ADC8</text>
<text x="29.5" y="108.4">ADC5</text>
<text x="29.5" y="110.9">ADC7</text>
<text x="29.5" y="109.7">ADC6</text>
<text x="63.5" y="110">ENC_CH2</text>
<text x="65.1" y="111.2">ENC_CH1</text>
<text x="147.8" y="113.5">Batt 1</text>
<text x="155.4" y="109.7">Batt</text>
<text x="200.5" y="113.5">Batt 1</text>
<text x="208.2" y="109.7">Batt</text>
<text x="140.2" y="114.7">Batt</text>
<text x="142.8" y="116">Motor4_R_PWM 2</text>
<text x="143" y="116.5">R21</text>
<text x="163.8" y="115.9">C30Motor4_R</text>
<text x="166.8" y="116.3">10</text>
<text x="183.2" y="114.7">MOTOR_BATT</text>
<text x="192.9" y="114.7">Batt</text>
<text x="195.5" y="116">Motor5_R_PWM 2</text>
<text x="195.7" y="116.5">R39</text>
<text x="216.5" y="115.9">C42Motor5_R</text>
<text x="219.5" y="116.3">10</text>
<text x="235.9" y="114.7">MOTOR_BATT</text>
<text x="165.2" y="121.1">Motor4_R</text>
<text x="168.3" y="121.2">GND5</text>
<text x="185.1" y="121.1">Motor4_R</text>
<text x="217.9" y="121.1">Motor5_R</text>
<text x="221" y="121.2">GND5</text>
<text x="237.8" y="121.1">Motor5_R</text>
<text x="256.4" y="125.2">MOTOR_BATT</text>
<text x="260.9" y="120.8">Batt</text>
<text x="52.6" y="130.3">Buzzer_PWM</text>
<text x="224.4" y="136.3">MOTOR_BATT</text>
<text x="24.6" y="140.6" transform="rotate(-90 24.6 140.6)">I2C2_SCL</text>
<text x="28.1" y="139.4" transform="rotate(-90 28.1 139.4)">I2C2_SDA</text>
<text x="161.5" y="142.9">330USART3_RX</text>
<text x="162.8" y="142">USART3_TX</text>
<text x="165.3" y="142.3">LED</text>
<text x="179.4" y="139.2">D+ +3.3V</text>
<text x="190.9" y="141.1">2 D-</text>
<text x="190.9" y="139.8">3 D+</text>
<text x="202.7" y="141.7">USART2_RX</text>
<text x="202.8" y="140.5">USART2_TX</text>
<text x="206.7" y="140.6">GND3</text>
<text x="224.8" y="138.9">SERVO_PWM</text>
<text x="55.5" y="144.9">ADRESS1</text>
<text x="55.5" y="148.7">ADRESS0</text>
<text x="71.1" y="144.9">ADRESS3</text>
<text x="71.1" y="148.7">ADRESS2</text>
<text x="261.9" y="150.3">Motor0_L</text>
<text x="261.9" y="154.1">Motor0_R</text>
<text x="275.9" y="154.1">Motor1_R</text>
<text x="275.9" y="150.3">Motor1_L</text>
<text x="106.3" y="161.4">LED_Blue</text>
<text x="261.9" y="160.5">Motor2_R</text>
<text x="261.9" y="156.6">Motor2_L</text>
<text x="275.9" y="160.5">Motor3_R</text>
<text x="275.9" y="156.6">Motor3_L</text>
<text x="95.6" y="164.9">SW0</text>
<text x="100" y="164.9">SW1</text>
<text x="105.7" y="162.7">LED_Green</text>
<text x="106.6" y="164">LED_Red</text>
<text x="153.1" y="164">SPI2_MOSI</text>
<text x="153.5" y="166.5">SPI2_SCK</text>
<text x="153.6" y="162.7">SPI2_NSS</text>
<text x="261.9" y="166.8">Motor4_R</text>
<text x="261.9" y="163">Motor4_L</text>
<text x="275.9" y="166.8">Motor5_R</text>
<text x="275.9" y="163">Motor5_L</text>
<text x="153.1" y="169">SPI2_MISO</text>
</g>
<g font-size=".9" fill="#008400">
<text x="181.7" y="21.9">PWR_FLAG</text>
<text x="234.4" y="21.9">PWR_FLAG</text>
<text x="181.7" y="40">PWR_FLAG</text>
<text x="234.4" y="40">PWR_FLAG</text>
<text x="181.7" y="61.6">PWR_FLAG</text>
<text x="234.4" y="61.6">PWR_FLAG</text>
<text x="181.7" y="79.7">PWR_FLAG</text>
<text x="234.4" y="79.7">PWR_FLAG</text>
<text x="181.7" y="101.3">PWR_FLAG</text>
<text x="234.4" y="101.3">PWR_FLAG</text>
<text x="181.7" y="119.4">PWR_FLAG</text>
<text x="234.4" y="119.4">PWR_FLAG</text>
</g>
<g font-size=".9" fill="#0000c2">
<text x="57.1" y="44.3">TIM2 CH2</text>
<text x="55.6" y="50.6">TIM3 CH1</text>
<text x="55.6" y="51.9">TIM3 CH2</text>
<text x="58.1" y="53.1">TIM1 CH1</text>
<text x="57.2" y="58.2">EMG is HIGH -&gt; EMG OFF</text>
<text x="58.1" y="57">TIM1 CH4</text>
<text x="49.4" y="62">50SERVO_PWM TIM2 CH1</text>
<text x="12.7" y="70.9">Brake is LOW -&gt; Brake</text>
<text x="58.1" y="73.5">TIM4 CH2</text>
<text x="58.1" y="72.2">TIM4 CH1</text>
</g>
<text font-size=".9" fill="#000084" x="160.7" y="170.4">GND8</text>
<g font-size=".7" fill="#840000">
<text x="27.4" y="10.9">1</text>
<text x="30.6" y="10.9">2</text>
<text x="32.2" y="16.3">2</text>
<text x="35.4" y="16.3">1</text>
<text x="157.9" y="12.8">2</text>
<text x="161.1" y="12.8">1</text>
<text x="210.6" y="12.8">2</text>
<text x="213.8" y="12.8">1</text>
<text x="157.9" y="30.9">2</text>
<text x="161.1" y="30.9">1</text>
<text x="210.6" y="30.9">2</text>
<text x="213.8" y="30.9">1</text>
<text x="19.6" y="46.5" transform="rotate(-90 19.6 46.5)">2</text>
<text x="19.6" y="49.7" transform="rotate(-90 19.6 49.7)">1</text>
<text x="157.9" y="52.5">2</text>
<text x="161.1" y="52.5">1</text>
<text x="210.6" y="52.5">2</text>
<text x="213.8" y="52.5">1</text>
<text x="157.9" y="70.6">2</text>
<text x="161.1" y="70.6">1</text>
<text x="210.6" y="70.6">2</text>
<text x="213.8" y="70.6">1</text>
<text x="267.5" y="75.1">2</text>
<text x="270.6" y="75.1">1</text>
<text x="157.9" y="92.2">2</text>
<text x="161.1" y="92.2">1</text>
<text x="210.6" y="92.2">2</text>
<text x="213.8" y="92.2">1</text>
<text x="266.8" y="96">1</text>
<text x="270" y="96">2</text>
<text x="157.9" y="110.3">2</text>
<text x="161.1" y="110.3">1</text>
<text x="210.6" y="110.3">2</text>
<text x="213.8" y="110.3">1</text>
<text x="60.8" y="126.5">2</text>
<text x="63.9" y="126.5">1</text>
<text x="192.5" y="137.3">2</text>
<text x="195.7" y="137.3">1</text>
<text x="263.3" y="178.9">2</text>
<text x="266.5" y="178.9">1</text>
</g>
<g font-size=".7" fill="#008484">
<text x="28.1" y="9.8">DIODE</text>
<text x="28.6" y="8.9">D30</text>
<text x="158.6" y="11.8">DIODE</text>
<text x="159.3" y="10.8">D9</text>
<text x="211.3" y="11.8">DIODE</text>
<text x="211.8" y="10.8">D15</text>
<text x="32.9" y="15.2">DIODE</text>
<text x="33.5" y="14.3">D7</text>
<text x="158.6" y="29.9">DIODE</text>
<text x="159.1" y="28.9">D10</text>
<text x="211.3" y="29.9">DIODE</text>
<text x="211.8" y="28.9">D16</text>
<text x="21.4" y="49" transform="rotate(-90 21.4 49)">DIODE</text>
<text x="22.4" y="48.3" transform="rotate(-90 22.4 48.3)">D1</text>
<text x="158.6" y="51.4">DIODE</text>
<text x="159.1" y="50.5">D11</text>
<text x="211.3" y="51.4">DIODE</text>
<text x="211.8" y="50.5">D17</text>
<text x="158.6" y="69.5">DIODE</text>
<text x="159.1" y="68.6">D12</text>
<text x="211.3" y="69.5">DIODE</text>
<text x="211.8" y="68.6">D18</text>
<text x="268.1" y="74">DIODE</text>
<text x="268.6" y="73">D21</text>
<text x="158.6" y="91.1">DIODE</text>
<text x="159.1" y="90.2">D13</text>
<text x="211.3" y="91.1">DIODE</text>
<text x="211.8" y="90.2">D19</text>
<text x="267.5" y="94.9">DIODE</text>
<text x="268" y="93.9">D27</text>
<text x="158.6" y="109.2">DIODE</text>
<text x="159.1" y="108.3">D14</text>
<text x="211.3" y="109.2">DIODE</text>
<text x="211.8" y="108.3">D20</text>
<text x="61.4" y="125.4">DIODE</text>
<text x="61.9" y="124.5">D28</text>
<text x="193.2" y="136.2">DIODE</text>
<text x="193.9" y="135.2">D8</text>
<text x="264" y="177.8">DIODE</text>
<text x="264.5" y="176.8">D29</text>
</g>
</g></defs>
<g fill="none" stroke="#840000" stroke-width=".13">
<path d="M5 5.3h287v199.9h-287zM6 6.2h285v198h-285zM8.1 19.6h1v2.6h-1zM8.6 19v.6M12.1 19v1.4M15.7 19.6h1v2.6h-1zM16.2 16.4h2.5M16.2 17.7h2.5M18.7 15.2h5.1v5.1h-5.1zM18.7 19h-2.5v.6M19.4 11h1.4M21.8 11h1.4"/>
<path d="M23.8 16.4h2.6M23.8 17.7h2.6M23.8 19h2.6M26.7 11h1.9M27 16.4h.2l.2-.2 .3 .1v.1l.3-.2 .2 .1 .1 .1 .2-.2 .2 .1 .1 .1 .2-.2 .2 .1 .1 .1h.2M27.6 17.7v1.4M28.6 10.4v1.3M29.8 11h1.9v.7h.7l-.7 .6-.6-.6h.6M30 5.3v.9M31.4 16.4h1.9M31.4 17.1v1.4M31.4 19.5v1.4"/>
<path d="M34.6 16.4h1.9M34.6 15.8v1.3M36.8 14.9h2v1.1h-2l-.3-.5zM39.4 16.1v.7h.6l-.6 .6-.7-.6h.7M40.6 16.1h1.3M40.6 18.7h1.3M43.1 11.4h2l.3 .6-.3 .6h-2zM43.9 17.5l-1.5 1M44.4 17.4h1.3M45.5 14.2h1v2.6h-1zM46 13.6v.6M46 16.8v.6"/>
<path d="M46.4 17.4h2.6M47.5 19.4h2l.3 .5-.3 .6h-2zM49 16.4v1.9M49.3 17.4h.9v2.5M49.3 16.5h1.2v1.8h-1.2M49.3 16.3v.5M49.3 17.1v.5M49.3 18v.5M50.2 13.6v2.9M50.2 13.6l-.4 .6M50.2 13.6l.3 .6M50.4 17.3h.3l-.2 .3z"/>
<path d="M50.8 17.5l-.5 .1M54.3 15.2v1.2M54.3 17.1v1.4M54.3 19.5v1.4M54.3 15.2l-.4 .6M54.3 15.2l.4 .6M54.6 16.4h2.5M55 5.3v.9M57.1 15.2h6.4v4.4h-6.4zM60.3 19.6v3.2h.7l-.7 .6-.6-.6h.6M63.5 16.4h2.5M66.4 15.2v1.2"/>
<path d="M66.4 17.1v1.4M66.4 19.5v1.4M66.4 15.2l-.4 .6M66.4 15.2l.3 .6M80 5.3v.9M92.4 19.3l3.8 1.9-3.8 1.9zM98.1 18.7h2.2M100 18h1.6M100 18a3.3 3.3 0 0 1 0 3.8M101.6 18a2.62 2.62 0 0 1 2.2 1.9M103.8 19.9a2.6 2.6 0 0 1-2.2 2M105 5.3v.9"/>
<path d="M122.9 15.7v2h.6l-.6 .6-.7-.6h.7M122.9 12l-.4 .6M122.9 12v2.7M122.9 12l.4 .6M127 15.8h5.1v7.6h-5.1zM129.5 12v3.8M129.5 12l-.3 .6M129.5 12l.4 .6M130 5.3v.9M141.7 18h1v2.6h-1zM142.2 17.4v.6M145.1 12.5v2h.6l-.6 .7-.6-.7h.6"/>
<path d="M145.1 10.1v1.4M149.5 16.1h1.3M149.5 18.7h1.3M150.8 14.9h8.9v10.1h-8.9zM155 5.3v.9M157.2 12.9h1.9M159.7 16.1h1.3M159.7 18.7h1.3M160.3 12.9h1.9M160.3 12.3v1.3M162.2 16.8v1.4M162.2 19.2v1.4"/>
<path d="M165.4 19.9h.7M166.1 19.4h2.5v1h-2.5zM168.6 19.9h3.2M169.2 18.7h2.6M171.8 16.1h8.9v11.5h-8.9zM180 5.3v.9M180.7 18.7h2.5M180.7 19.9h2.5M180.7 17.4h2.5M194.1 18h1v2.6h-1zM194.6 17.4v.6M197.8 12.5v2h.6l-.6 .7-.6-.7h.6"/>
<path d="M197.8 10.1v1.4M202.2 16.1h1.3M202.2 18.7h1.3M203.5 14.9h8.9v10.1h-8.9zM205 5.3v.9M209.9 12.9h1.9M212.4 16.1h1.3M212.4 18.7h1.3M213 12.3v1.3M213 12.9h1.9M214.9 16.8v1.4M214.9 19.2v1.4"/>
<path d="M218.1 19.9h.7M218.8 19.4h2.5v1h-2.5zM221.3 19.9h3.2M221.9 18.7h2.6M224.5 16.1h8.9v11.5h-8.9zM230 5.3v.9M233.4 18.7h2.5M233.4 19.9h2.5M233.4 17.4h2.5M255 5.3v.9M256.9 12.9h6.3v6.4h-6.3zM268.3 6h.3"/>
<path d="M280 5.3v.9M5 30.2h1M8.6 22.2v1.2h.6l-.6 .7-.7-.7h.7M12.1 21.4v1.4M14 33.9v1.4M14 36.3v1.4M14.3 33.3h.9M16.2 37.7v.6h.6l-.6 .7-.6-.7h.6M16.2 22.2v.6M17.1 33.3h1M18.4 33.9v1.4M18.4 36.3v1.4"/>
<path d="M27.6 20.1v1.4M31.4 21.5v.7h.7l-.7 .6-.6-.6h.6M34.3 30.1v2.7M34.3 33.8v1.4M34.3 30.1l-.4 .6M34.3 30.1l.4 .6M38.7 31.4v1.4M38.7 33.8v1.4M39.1 39.3l-.4 .6M39.1 39.3v2.5M39.1 39.3l.3 .6M43.2 31.4v1.4"/>
<path d="M43.2 33.8v1.4M47.6 31.4v1.4M47.6 33.8v1.4M52.1 31.4v1.4M52.1 33.8v1.4M56.5 33.8v2h.6l-.6 .6-.6-.6h.6M56.5 31.4v1.4M90.5 21.2h1.9M90.5 34.5h1.9M92.4 32.6l3.8 1.9-3.8 1.9zM96.8 21.2h3.5M96.8 34.5h3.5"/>
<path d="M98.1 25.3h2.2M98.1 27.9h2.2M98.1 32h2.2M98.1 38.7h2.2M100 31.4h1.6a2.62 2.62 0 0 1 2.2 1.9M100 38h1.6a2.62 2.62 0 0 1 2.2 1.9M100 28.5h1.6M100 24.7h1.6M100 21.8h1.6M100 24.7a3.3 3.3 0 0 1 0 3.8M100 31.4a3.3 3.3 0 0 1 0 3.8M100 38a3.3 3.3 0 0 1 0 3.8"/>
<path d="M101.6 24.7a2.62 2.62 0 0 1 2.2 1.9M103.8 26.6a2.6 2.6 0 0 1-2.2 1.9M103.8 33.3a2.6 2.6 0 0 1-2.2 1.9h-1.6M103.8 39.9a2.6 2.6 0 0 1-2.2 2l-1.6-.1M104.5 33.3h1.2M104.5 26.6h1.2M122.9 35v2.1h.6l-.6 .6-.7-.6h.7M122.9 31.4v2.6M122.9 31.4l-.4 .6M122.9 31.4l.4 .6M127 35.2h5.1v7.6h-5.1zM129.5 23.4v3.2h.7l-.7 .6-.6-.6h.6"/>
<path d="M129.5 31.4v3.8M129.5 31.4l-.3 .6M129.5 31.4l.4 .6M141.4 36.1h1v2.6h-1zM141.9 35.5v.6M141.9 38.7v.6M142.2 20.6v.6M145.1 30.6v2h.6l-.6 .7-.6-.7h.6M145.1 28.2v1.4M149.5 25v.6h.7l-.7 .7-.6-.7h.6M149.5 21.2h1.3M149.5 23.7h1.3"/>
<path d="M149.5 34.2h1.3M149.5 36.8h1.3M149.5 39.3h1.3M150.8 33h8.9v10.1h-8.9zM157.2 31h1.9M159.7 21.2h1.3M159.7 23.7h1.3M159.7 34.2h1.3M159.7 36.8h1.3M159.7 39.3h1.3M160.3 30.4v1.3M160.3 31h1.9"/>
<path d="M162.2 34.9v1.4M162.2 37.3v1.4M165.4 22.5h.7M165.4 38h.7M166.1 22h2.5v1h-2.5zM166.1 37.5h2.5v1h-2.5zM168.6 22.5h3.2M168.6 38h3.2M169.2 23.7h2.6M169.2 25h2.6M169.2 36.8h2.6M171.8 34.2h8.9v11.5h-8.9z"/>
<path d="M171.8 39.3h-2.6v.6h.7l-.7 .7-.6-.7h.6M171.8 21.2h-2.6v.6h.7l-.7 .7-.6-.7h.6M180.7 21.2h2.5M180.7 23.7h2.5M180.7 25h2.5M180.7 22.5h2.5M180.7 26.3h2.5M180.7 36.8h2.5M180.7 39.3h2.5M180.7 38h2.5M180.7 35.5h2.5M184.1 23.1l.6-.3-.6-.3-.5 .3 .5 .3v.6"/>
<path d="M184.1 23.7h.1M194.1 36.1h1v2.6h-1zM194.6 20.6v.6M194.6 35.5v.6M194.6 38.7v.6M197.8 30.6v2h.6l-.6 .7-.6-.7h.6M197.8 28.2v1.4M202.2 25v.6h.7l-.7 .7-.6-.7h.6M202.2 21.2h1.3M202.2 23.7h1.3M202.2 34.2h1.3M202.2 36.8h1.3"/>
<path d="M202.2 39.3h1.3M203.5 33h8.9v10.1h-8.9zM209.9 31h1.9M212.4 21.2h1.3M212.4 23.7h1.3M212.4 34.2h1.3M212.4 36.8h1.3M212.4 39.3h1.3M213 30.4v1.3M213 31h1.9M214.9 34.9v1.4M214.9 37.3v1.4"/>
<path d="M218.1 22.5h.7M218.1 38h.7M218.8 22h2.5v1h-2.5zM218.8 37.5h2.5v1h-2.5zM221.3 22.5h3.2M221.3 38h3.2M221.9 23.7h2.6M221.9 25h2.6M221.9 36.8h2.6M224.5 34.2h8.9v11.5h-8.9zM224.5 21.2h-2.6v.6h.7l-.7 .7-.6-.7h.6M224.5 39.3h-2.6v.6h.7l-.7 .7-.6-.7h.6"/>
<path d="M233.4 21.2h2.5M233.4 23.7h2.5M233.4 25h2.5M233.4 22.5h2.5M233.4 26.3h2.5M233.4 36.8h2.5M233.4 39.3h2.5M233.4 38h2.5M233.4 35.5h2.5M236.9 23.1l.5-.3-.5-.3-.6 .3 .6 .3v.6M236.9 23.7h.1M256.9 28.2h6.3v6.3h-6.3z"/>
<path d="M256.9 35.8h6.3v6.4h-6.3zM256.9 20.6h6.3v6.3h-6.3zM269.6 31.4l-.4 .6M269.6 31.4v1.2M269.6 31.4l.3 .6M270.8 31.4v.6h.7l-.7 .6-.6-.6h.6M271.8 31.4h1.9M271.8 32.6h1.9M273.7 30.7h1.3v2.6h-1.3zM273.7 32.6h.6v.1h-.6zM273.7 31.3h.6v.1h-.6zM291 30.2h1"/>
<path d="M5 55.3h1M8.9 43.4h1.3v7.6h-1.3zM9.5 49.1h.7v.1h-.7zM9.5 50.3h.7v.2h-.7zM9.5 47.8h.7v.1h-.7zM9.5 45.3h.7v.1h-.7zM9.5 44h.7v.1h-.7zM9.5 46.5h.7v.2h-.7zM10.2 44.1h1.9M10.2 45.3h4M10.2 46.6h1.9M10.2 47.9h1.9"/>
<path d="M10.2 49.1h1.9M10.2 50.4h1.9M12.4 44.1v.6h.6l-.6 .6-.7-.6h.7M12.7 56.4h1.3M14 55.8h2.5M14.6 44.7a1.58 1.58 0 0 1 2.5 0M15.2 54.9v.9M16.5 56.4h1.3M17.6 45.3h2.1v1.9M19 48.5h1.3M19.7 48.5v1.9M23.5 49.1l-.4 .7"/>
<path d="M23.5 49.1v1.3M23.5 49.1l.4 .7M27.1 46.3h1v2.5h-1zM27.6 45.7v.6M27.6 48.8v.7M30.5 50.6v2h.6l-.6 .7-.7-.7h.7M30.5 48.2v1.4M32.7 58.4h1.3M32.7 57.1h1.3M32.7 43.1h1.3M34 41.8h15.2v42h-15.2zM90.5 49.1h1.9"/>
<path d="M92.4 47.2l3.8 1.9-3.8 1.9zM96.8 49.1h3.5M98.1 46.6h2.2M98.1 55.8h2.2M98.1 41.2h2.2M98.1 53.3h2.2M98.1 59.9h2.2M100 52.6h1.6a2.62 2.62 0 0 1 2.2 1.9M100 59.3h1.6a2.62 2.62 0 0 1 2.2 1.9 2.58 2.58 0 0 1-2.2 1.9h-1.6M100 46h1.6a2.62 2.62 0 0 1 2.2 1.9M100 52.6a3.3 3.3 0 0 1 0 3.8M100 59.3a3.3 3.3 0 0 1 0 3.8"/>
<path d="M100 46a3.3 3.3 0 0 1 0 3.8M103.8 54.6a2.6 2.6 0 0 1-2.2 1.9l-1.6-.1M103.8 47.9a2.6 2.6 0 0 1-2.2 1.9h-1.6M104.5 54.5h1.2M122.9 54.4v2h.6l-.6 .7-.7-.7h.7M122.9 50.7v2.7M122.9 50.7l-.4 .7M122.9 50.7l.4 .7M127 54.5h5.1v7.7h-5.1zM129.5 42.8v3.2h.7l-.7 .6-.6-.6h.6M129.5 50.7v3.8M129.5 50.7l-.3 .7"/>
<path d="M129.5 50.7l.4 .7M141.4 57.7h1v2.6h-1zM141.9 57.1v.6M145.1 52.2v2h.6l-.6 .7-.6-.7h.6M145.1 49.8v1.4M149.5 43.1v.6h.7l-.7 .7-.6-.7h.6M149.5 58.4h1.3M149.5 41.8h1.3M149.5 55.8h1.3M150.8 54.5h8.9v10.2h-8.9zM157.2 52.6h1.9M159.7 58.4h1.3"/>
<path d="M159.7 41.8h1.3M159.7 55.8h1.3M160.3 52v1.3M160.3 52.6h1.9M162.2 56.4v1.4M162.2 58.9v1.4M165.4 59.6h.7M165.4 40.6h.7M166.1 59.1h2.5v1h-2.5zM166.1 40.1h2.5v1h-2.5zM168.6 59.6h3.2M168.6 40.6h3.2"/>
<path d="M169.2 58.4h2.6M169.2 41.8h2.6M169.2 43.1h2.6M171.8 55.8h8.9v11.4h-8.9zM180.7 58.4h2.5M180.7 59.6h2.5M180.7 57.1h2.5M180.7 40.6h2.5M180.7 41.8h2.5M180.7 43.1h2.5M180.7 44.4h2.5M184.1 41.2l.6-.3-.6-.3-.5 .3 .5 .3v.6"/>
<path d="M184.1 41.8h.1M194.1 57.7h1v2.6h-1zM194.6 57.1v.6M197.8 52.2v2h.6l-.6 .7-.6-.7h.6M197.8 49.8v1.4M202.2 43.1v.6h.7l-.7 .7-.6-.7h.6M202.2 58.4h1.3M202.2 41.8h1.3M202.2 55.8h1.3M203.5 54.5h8.9v10.2h-8.9zM209.9 52.6h1.9M212.4 58.4h1.3"/>
<path d="M212.4 41.8h1.3M212.4 55.8h1.3M213 52v1.3M213 52.6h1.9M214.9 56.4v1.4M214.9 58.9v1.4M218.1 59.6h.7M218.1 40.6h.7M218.8 59.1h2.5v1h-2.5zM218.8 40.1h2.5v1h-2.5zM221.3 59.6h3.2M221.3 40.6h3.2"/>
<path d="M221.9 58.4h2.6M221.9 41.8h2.6M221.9 43.1h2.6M224.5 55.8h8.9v11.4h-8.9zM233.4 58.4h2.5M233.4 59.6h2.5M233.4 57.1h2.5M233.4 40.6h2.5M233.4 41.8h2.5M233.4 43.1h2.5M233.4 44.4h2.5M236.9 41.2l.5-.3-.5-.3-.6 .3 .6 .3v.6"/>
<path d="M236.9 41.8h.1M256.9 43.7h6.3v6.4h-6.3zM256.9 51.7h6.3v6.3h-6.3zM291 55.3h1M13.3 60.3h1.4M15.7 60.3h1.4M17.8 60.3v.6h.6l-.6 .6-.7-.6h.7M32.7 63.4h1.3M32.7 64.7h1.3M32.7 79.9h1.3M90.5 62.5h1.9M90.5 77.1h1.9"/>
<path d="M92.4 60.6l3.8 1.9-3.8 1.9zM92.4 75.2l3.8 1.9-3.8 1.9zM96.8 62.5h3.5M96.8 77.1h3.5M98.1 66.6h2.2M98.1 69.1h2.2M98.1 74.5h2.2M100 66h1.6a2.62 2.62 0 0 1 2.2 1.9M100 73.9h1.6a2.62 2.62 0 0 1 2.2 1.9 2.58 2.58 0 0 1-2.2 1.9h-1.6M100 66a3.3 3.3 0 0 1 0 3.8M100 73.9a3.3 3.3 0 0 1 0 3.8M103.8 67.9a2.6 2.6 0 0 1-2.2 1.9h-1.6"/>
<path d="M104.5 61.2h1.2M122.9 73.8v2h.6l-.6 .6-.7-.6h.7M122.9 70.1v2.7M122.9 70.1l-.4 .6M122.9 70.1l.4 .6M127 73.9h5.1v7.6h-5.1zM129.5 62.2v3.1h.7l-.7 .7-.6-.7h.6M129.5 70.1v3.8M129.5 70.1l-.3 .6M129.5 70.1l.4 .6M141.4 75.8h1v2.6h-1zM141.9 60.3v.6"/>
<path d="M141.9 75.2v.6M141.9 78.4v.6M145.1 70.3v2h.6l-.6 .7-.6-.7h.6M145.1 67.9v1.4M149.5 64.7v.6h.7l-.7 .7-.6-.7h.6M149.5 60.9h1.3M149.5 63.4h1.3M149.5 73.9h1.3M149.5 76.4h1.3M149.5 79h1.3M150.8 72.6h8.9v10.2h-8.9zM157.2 70.7h1.9"/>
<path d="M159.7 60.9h1.3M159.7 63.4h1.3M159.7 73.9h1.3M159.7 76.4h1.3M159.7 79h1.3M160.3 70.1v1.3M160.3 70.7h1.9M162.2 74.5v1.4M162.2 77v1.4M165.4 62.2h.7M165.4 77.7h.7M166.1 77.2h2.5v1h-2.5z"/>
<path d="M166.1 61.7h2.5v1h-2.5zM166.1 79.8h2.5v1h-2.5zM168.6 62.2h3.2M168.6 77.7h3.2M169.2 63.4h2.6M169.2 64.7h2.6M169.2 76.4h2.6M171.8 73.9h8.9v11.4h-8.9zM171.8 60.9h-2.6v.6h.7l-.7 .7-.6-.7h.6M171.8 79h-2.6v.6h.7l-.7 .7-.6-.7h.6M180.7 60.9h2.5M180.7 63.4h2.5"/>
<path d="M180.7 64.7h2.5M180.7 62.2h2.5M180.7 66h2.5M180.7 76.4h2.5M180.7 79h2.5M180.7 77.7h2.5M180.7 75.2h2.5M184.1 62.8l.6-.3-.6-.3-.5 .3 .5 .3v.6M184.1 63.4h.1M194.1 75.8h1v2.6h-1zM194.6 60.3v.6M194.6 75.2v.6"/>
<path d="M194.6 78.4v.6M197.8 70.3v2h.6l-.6 .7-.6-.7h.6M197.8 67.9v1.4M202.2 64.7v.6h.7l-.7 .7-.6-.7h.6M202.2 60.9h1.3M202.2 63.4h1.3M202.2 73.9h1.3M202.2 76.4h1.3M202.2 79h1.3M203.5 72.6h8.9v10.2h-8.9zM209.9 70.7h1.9M212.4 60.9h1.3"/>
<path d="M212.4 63.4h1.3M212.4 73.9h1.3M212.4 76.4h1.3M212.4 79h1.3M213 70.1v1.3M213 70.7h1.9M214.9 74.5v1.4M214.9 77v1.4M218.1 62.2h.7M218.1 77.7h.7M218.8 61.7h2.5v1h-2.5zM218.8 77.2h2.5v1h-2.5z"/>
<path d="M218.8 79.8h2.5v1h-2.5zM221.3 62.2h3.2M221.3 77.7h3.2M221.9 63.4h2.6M221.9 64.7h2.6M221.9 76.4h2.6M224.5 73.9h8.9v11.4h-8.9zM224.5 60.9h-2.6v.6h.7l-.7 .7-.6-.7h.6M224.5 79h-2.6v.6h.7l-.7 .7-.6-.7h.6M233.4 60.9h2.5M233.4 63.4h2.5M233.4 64.7h2.5"/>
<path d="M233.4 62.2h2.5M233.4 66h2.5M233.4 76.4h2.5M233.4 79h2.5M233.4 77.7h2.5M233.4 75.2h2.5M236.9 62.8l.5-.3-.5-.3-.6 .3 .6 .3v.6M236.9 63.4h.1M260.7 65.8h.5M261 65.5v.5M261.6 65v1.4M261.6 67.2v1.6"/>
<path d="M263.5 77.7v1.3M263.5 77.7l.4 .7M263.5 77.7l-.4 .7M265.8 65.8h.5M266.1 79.6h5v3.8h-5zM266.1 65.5v.5M266.7 65v1.4M266.7 67.2v1.6M266.7 73.9v1.3h1.9M266.7 73.9l-.4 .6M266.7 73.9l.4 .6M269.9 75.2h1.9"/>
<path d="M269.9 74.5v1.3M271.5 65v1.4M271.5 67.4v1.4M271.8 74.5l.5-.3-.5-.3-.5 .3 .5 .3v.7M271.8 75.2h.1M275.9 67.4v2.1h.6l-.6 .6-.6-.6h.6M275.9 65v1.4M5 80.2h1M32.7 82.5h1.3M32.7 81.2h1.3M44.1 85v.7h.7l-.7 .6-.6-.6h.6M90.5 90.4h1.9"/>
<path d="M92.4 88.5l3.8 1.9-3.8 1.9zM96.8 90.4h3.5M98.1 81.2h2.2M98.1 83.8h2.2M98.1 87.9h2.2M98.1 94.5h2.2M98.1 97.1h2.2M100 80.6h1.6a2.62 2.62 0 0 1 2.2 1.9M100 87.2h1.6a2.62 2.62 0 0 1 2.2 1.9M100 97.7h1.6M100 93.9h1.6M100 80.6a3.3 3.3 0 0 1 0 3.8"/>
<path d="M100 87.3a3.3 3.3 0 0 1 0 3.7M100 93.9a3.3 3.3 0 0 1 0 3.8M101.6 93.9a2.62 2.62 0 0 1 2.2 1.9M103.8 82.5a2.6 2.6 0 0 1-2.2 1.9h-1.6M103.8 89.2a2.6 2.6 0 0 1-2.2 1.9h-1.6M103.8 95.8a2.6 2.6 0 0 1-2.2 1.9M104.5 82.5h1.2M104.5 89.1h1.2M129.5 81.5v3.2h.7l-.7 .6-.6-.6h.6M141.4 97.4h1v2.5h-1zM141.9 96.8v.6M141.9 99.9v.7"/>
<path d="M145.1 91.9v2h.6l-.6 .6-.6-.6h.6M145.1 89.5v1.4M149.5 82.8v.6h.7l-.7 .7-.6-.7h.6M149.5 95.5h1.3M149.5 98h1.3M149.5 81.5h1.3M150.8 94.2h8.9v10.2h-8.9zM157.2 92.3h1.9M159.7 95.5h1.3M159.7 98h1.3M159.7 81.5h1.3M160.3 92.3h1.9"/>
<path d="M160.3 91.7v1.3M162.2 96.1v1.4M162.2 98.5v1.4M165.4 80.3h.7M165.4 99.3h.7M166.1 98.8h2.5v1h-2.5zM168.6 80.3h3.2M168.6 99.3h3.2M169.2 98h2.6M169.2 81.5h2.6M169.2 82.8h2.6M171.8 95.5h8.9v11.4h-8.9z"/>
<path d="M180.7 80.3h2.5M180.7 98h2.5M180.7 99.3h2.5M180.7 96.8h2.5M180.7 81.5h2.5M180.7 82.8h2.5M180.7 84.1h2.5M184.1 80.9l.6-.3-.6-.3-.5 .3 .5 .3v.6M184.1 81.5h.1M194.1 97.4h1v2.5h-1zM194.6 96.8v.6M194.6 99.9v.7"/>
<path d="M197.8 91.9v2h.6l-.6 .6-.6-.6h.6M197.8 89.5v1.4M202.2 82.8v.6h.7l-.7 .7-.6-.7h.6M202.2 95.5h1.3M202.2 98h1.3M202.2 81.5h1.3M203.5 94.2h8.9v10.2h-8.9zM209.9 92.3h1.9M212.4 95.5h1.3M212.4 98h1.3M212.4 81.5h1.3M213 91.7v1.3"/>
<path d="M213 92.3h1.9M214.9 96.1v1.4M214.9 98.5v1.4M218.1 80.3h.7M218.1 99.3h.7M218.8 98.8h2.5v1h-2.5zM221.3 80.3h3.2M221.3 99.3h3.2M221.9 98h2.6M221.9 81.5h2.6M221.9 82.8h2.6M224.5 95.5h8.9v11.4h-8.9z"/>
<path d="M233.4 80.3h2.5M233.4 98h2.5M233.4 99.3h2.5M233.4 96.8h2.5M233.4 81.5h2.5M233.4 82.8h2.5M233.4 84.1h2.5M236.9 80.9l.5-.3-.5-.3-.6 .3 .6 .3v.6M236.9 81.5h.1M254 97.4h1.3M255.3 99.9h-1.3v.7h.6l-.6 .6-.6-.6h.6M255.3 97.7l2 .8"/>
<path d="M256.5 97.1v1.1M257.8 98.7h1.3M258.9 95.2h1v2.5h-1zM259.4 94.5v.7M259.4 97.7v.7M259.7 98.7h2.7M261.6 88.8l.5-.3-.5-.3-.5 .3 .5 .3v.7M261.6 89.5h.1M262.4 97.7v1.9M262.6 98.7h.9v2.5M262.6 97.8h1.3v1.8h-1.3M262.6 97.5v.5"/>
<path d="M262.6 98.4v.5M262.6 99.3v.5M263.5 96.1v1.7M263.5 80.9h2.6M263.5 82.2h2.6M263.5 92h4.5M263.5 88.2h2.6M263.7 98.5h.4l-.2 .4zM264.2 98.8l-.5 .1M266.1 86.9h5v6.4h-5zM266.1 96.1h1.9M267.3 88.8v.7h-3.8"/>
<path d="M267.3 87.6l1.9 .6h4.5M268 90.7h1.2v1.9h-1.2zM268 90.7l1.2 1.9M268 95.5v1.3M269.2 92h4.5M269.2 96.1h1.9M271 99.9v1.9M271.1 80.9h2.6M271.1 82.2h2.6M271.2 99.8v.5M272.1 98.4v1.6M277.2 98.4v2.1"/>
<path d="M291 80.2h1M5 105.3h1M26.4 101.5h1.2v12.7h-1.2zM27 109.7h.6v.1h-.6zM27 111h.6v.1h-.6zM27 112.3h.6v.1h-.6zM27 113.5h.6v.2h-.6zM27 108.5h.6v.1h-.6zM27 105.9h.6v.1h-.6zM27 104.6h.6v.2h-.6zM27 103.4h.6v.1h-.6zM27 102.1h.6v.1h-.6z"/>
<path d="M27 107.2h.6v.1h-.6zM27.6 113.6h1.9M27.6 102.2h1.9M27.6 103.4h1.9M27.6 104.7h1.9M27.6 106h1.9M27.6 107.2h1.9M27.6 108.5h1.9M27.6 109.8h1.9M27.6 111.1h1.9M27.6 112.3h1.9M34.3 113.6h1.9"/>
<path d="M34.3 100.9v1.3h1.9M34.3 103.4h1.9M34.3 104.7h1.9M34.3 106h1.9M34.3 107.2h1.9M34.3 108.5h1.9M34.3 109.8h1.9M34.3 111.1h1.9M34.3 112.3h1.9M34.3 100.9l-.4 .6M34.3 100.9l.4 .6M36.2 101.5h2.5v12.7h-2.5z"/>
<path d="M36.2 109.7h.6v.1h-.6zM36.2 111h.6v.1h-.6zM36.2 112.3h.6v.1h-.6zM36.2 113.5h.6v.2h-.6zM36.2 108.5h.6v.1h-.6zM36.2 105.9h.6v.1h-.6zM36.2 104.6h.6v.2h-.6zM36.2 103.4h.6v.1h-.6zM36.2 102.1h.6v.1h-.6zM36.2 107.2h.6v.1h-.6zM38.1 109.7h.6v.1h-.6zM38.1 111h.6v.1h-.6z"/>
<path d="M38.1 112.3h.6v.1h-.6zM38.1 113.5h.6v.2h-.6zM38.1 108.5h.6v.1h-.6zM38.1 105.9h.6v.1h-.6zM38.1 104.6h.6v.2h-.6zM38.1 103.4h.6v.1h-.6zM38.1 102.1h.6v.1h-.6zM38.1 107.2h.6v.1h-.6zM38.7 113.6h1.9v.6h.7l-.7 .7-.6-.7h.6M38.7 102.2h1.9M38.7 103.4h1.9M38.7 104.7h1.9"/>
<path d="M38.7 106h1.9M38.7 107.2h1.9M38.7 108.5h1.9M38.7 109.8h1.9M38.7 111.1h1.9M38.7 112.3h1.9M55.1 104.1h1v2.5h-1zM55.6 100.9v1.3M55.6 103.4v.7M55.6 106.6v.6M55.6 100.9l-.4 .6M55.6 100.9l.3 .6"/>
<path d="M58.2 102.8h1v2.5h-1zM58.7 102.2v.6M58.7 105.3v.7M58.9 107.9h1v2.5h-1zM58.9 112.3h1v2.6h-1zM59.4 114.9v1.2h.6l-.6 .7-.7-.7h.7M59.4 107.2v.7M59.4 110.4v.7M59.4 111.7v.6M61.6 102.2v1.2h1.4M61.6 102.2l-.4 .6M61.6 102.2l.4 .6"/>
<path d="M62.4 106.6h1v2.6h-1zM62.4 111.1h1v2.5h-1zM62.9 113.6v1.3h.6l-.6 .6-.7-.6h.7M62.9 106v.6M62.9 109.2v.6M62.9 110.4v.7M64 103.4h1.4M65.7 103.4v.7h.7l-.7 .6-.6-.6h.6M66 103.4h1.9M66 104.7h1.9M66 106h1.9M66 107.2h1.9"/>
<path d="M67.9 102.8h1.3v5.1h-1.3zM67.9 107.2h.7v.1h-.7zM67.9 105.9h.7v.1h-.7zM67.9 103.4h.7v.1h-.7zM67.9 104.6h.7v.2h-.7zM141.4 115.5h1v2.5h-1zM141.9 114.9v.6M141.9 118v.7M145.1 110v2h.6l-.6 .6-.6-.6h.6M145.1 107.6v1.4M149.5 104.4v.6h.7l-.7 .7-.6-.7h.6M149.5 100.6h1.3"/>
<path d="M149.5 103.1h1.3M149.5 113.6h1.3M149.5 116.1h1.3M149.5 118.7h1.3M150.8 112.3h8.9v10.2h-8.9zM157.2 110.4h1.9M159.7 100.6h1.3M159.7 103.1h1.3M159.7 113.6h1.3M159.7 116.1h1.3M159.7 118.7h1.3M160.3 110.4h1.9"/>
<path d="M160.3 109.8v1.3M162.2 114.2v1.4M162.2 116.6v1.4M165.4 119.9h.7M165.4 101.8h.7M165.4 117.4h.7M166.1 116.9h2.5v1h-2.5zM166.1 119.4h2.5v1.1h-2.5zM166.1 101.3h2.5v1.1h-2.5zM168.6 119.9h3.2M168.6 101.8h3.2M168.6 117.4h3.2"/>
<path d="M169.2 103.1h2.6M169.2 104.4h2.6M169.2 116.1h2.6M171.8 113.6h8.9v11.4h-8.9zM171.8 118.7h-2.6v.6h.7l-.7 .6-.6-.6h.6M171.8 100.6h-2.6v.6h.7l-.7 .6-.6-.6h.6M180.7 119.9h2.5M180.7 100.6h2.5M180.7 103.1h2.5M180.7 104.4h2.5M180.7 101.8h2.5M180.7 105.7h2.5"/>
<path d="M180.7 116.1h2.5M180.7 118.7h2.5M180.7 117.4h2.5M180.7 114.9h2.5M184.1 102.5l.6-.3-.6-.4-.5 .4 .5 .3v.6M184.1 103.1h.1M194.1 115.5h1v2.5h-1zM194.6 114.9v.6M194.6 118v.7M197.8 110v2h.6l-.6 .6-.6-.6h.6M197.8 107.6v1.4M202.2 104.4v.6h.7l-.7 .7-.6-.7h.6"/>
<path d="M202.2 100.6h1.3M202.2 103.1h1.3M202.2 113.6h1.3M202.2 116.1h1.3M202.2 118.7h1.3M203.5 112.3h8.9v10.2h-8.9zM209.9 110.4h1.9M212.4 100.6h1.3M212.4 103.1h1.3M212.4 113.6h1.3M212.4 116.1h1.3M212.4 118.7h1.3"/>
<path d="M213 109.8v1.3M213 110.4h1.9M214.9 114.2v1.4M214.9 116.6v1.4M218.1 119.9h.7M218.1 101.8h.7M218.1 117.4h.7M218.8 119.4h2.5v1.1h-2.5zM218.8 101.3h2.5v1.1h-2.5zM218.8 116.9h2.5v1h-2.5zM221.3 119.9h3.2M221.3 101.8h3.2"/>
<path d="M221.3 117.4h3.2M221.9 103.1h2.6M221.9 104.4h2.6M221.9 116.1h2.6M224.5 113.6h8.9v11.4h-8.9zM224.5 118.7h-2.6v.6h.7l-.7 .6-.6-.6h.6M224.5 100.6h-2.6v.6h.7l-.7 .6-.6-.6h.6M233.4 119.9h2.5M233.4 100.6h2.5M233.4 103.1h2.5M233.4 104.4h2.5M233.4 101.8h2.5"/>
<path d="M233.4 105.7h2.5M233.4 116.1h2.5M233.4 118.7h2.5M233.4 117.4h2.5M233.4 114.9h2.5M236.9 102.5l.5-.3-.5-.4-.6 .4 .6 .3v.6M236.9 103.1h.1M262.6 115.2l-.4 .6M262.6 115.2v1.3h.6M262.6 115.2l.4 .6M263.2 115.9h2.5v1.1h-2.5zM265.7 116.5h4.5"/>
<path d="M267.7 115.8l1.2 .7-1.2 .6zM267.8 101.5h1v2.6h-1zM268.3 104.1v.6M268.9 115.8v1.3M269.9 115.7v-.4h-.3h.3l-.7 .8M270.6 115.7v-.4h-.4h.4l-.8 .8M271 100.9h-2.7v.6M271.2 100.9h.9v2.5M271.2 100h1.3v1.8h-1.3M271.2 100.6v.5M271.2 101.5v.5M272.2 100.6l.5 .2"/>
<path d="M272.5 100.7l.2 .3h-.4zM276.5 100.9a1.58 1.58 0 0 0 0 2.5M277.2 103.9v2.7h.6l-.6 .6-.7-.6h.7M291 105.3h1M5 130.2h1M24.3 133.3h1v2.5h-1zM24.8 127.6v1.2M24.8 132.6v.7M24.8 135.8v.7M24.8 127.6l-.4 .6M24.8 127.6l.3 .6M27.7 132h1.1v2.6h-1.1z"/>
<path d="M28.3 131.4v.6M28.3 134.6v.6M31.1 133.9h1.4M31.7 128.8h1.4M31.7 130.1h1.4M33.5 133.9h1.4M34.2 128.8h3.9M34.2 130.1h3.9M35.2 133.9v.7h.7l-.7 .6-.6-.6h.6M35.6 127.6h2.5M35.6 131.4h2.5M35.6 132.6h2.5"/>
<path d="M35.6 133.9h2.5M35.6 135.2h2.5M35.6 136.5h2.5M35.6 137.7h2.5M38.1 126.3h6.3v12.7h-6.3zM58.1 130.4h.6M58.7 129.9h2.6v1h-2.6zM60 126.6h1.9M61.3 130.4h3.5M63.2 126.6h1.9M63.2 126v1.2M64.8 130.7l.9 1v1.3h.7"/>
<path d="M65.4 125.3l-.4 .7M65.4 125.3v1.3M65.4 125.3l.4 .7M65.7 126.6h1.3M66.4 132.5h2.5v1h-2.5zM67 126h1.8v2.5h-1.8zM67 127.9h-1.3v1.3l-.9 .9M68.8 126l1.2-1.3v5.1l-1.2-1.3M68.9 133h.6v.6h.7l-.7 .6-.6-.6h.6M149.5 122.5v.6h.7l-.7 .7-.6-.7h.6M149.5 121.2h1.3M155.9 138.2v2.1h.6l-.6 .6-.6-.6h.6"/>
<path d="M155.9 134.6v2.6M155.9 134.6l-.4 .6M155.9 134.6l.4 .6M159.7 121.2h1.3M160.3 137.1v1.3M160.3 139.3h.7M160.3 137.1l-.3 .6M160.3 137.1l.4 .6M161 138.8h2.5v1h-2.5zM161 139.8h2.5v1h-2.5zM163.5 139.3h1.9M165.4 139.6l1.3 .7-1.3 .6z"/>
<path d="M165.4 138.7l1.3 .6-1.3 .6zM166.7 139.3h3.8M166.7 138.7v2.2M167.7 139.5v-.4h-.4h.4l-.8 .8M167.7 138.6v-.4h-.4h.4l-.8 .7M168 138.4h2.5M168.3 139.5v-.4h-.3h.3l-.7 .8M168.3 138.6v-.4h-.3h.3l-.7 .7M169.2 121.2h2.6M169.2 122.5h2.6M170.5 137.7h6.3v7h-6.3zM176.8 138.4h2.6"/>
<path d="M176.8 139.3h2.6M180.7 121.2h2.5M180.7 122.5h2.5M180.7 123.8h2.5M181.9 139.9l-.4 .7M181.9 139.9v1.3M181.9 139.9l.4 .7M184.1 120.6l.6-.3-.6-.4-.5 .4 .5 .3v.6M184.1 121.2h.1M184.1 138.4v.6h.7l-.7 .6-.6-.6h.6M185.4 136.1h5.1v7.7h-5.1zM185.6 137h1.7v.2l-.2 .5h-1.4z"/>
<path d="M186.7 138.9h.3l.3 .6h.7M187 138.9h1.3M187.6 138.2h-.3l-.6 .7h-.3M190.1 139.9h.4v.1h-.4zM190.1 137.3h.4v.2h-.4zM190.5 137.4h3.2M190.5 139.9h1.3M194.9 136.8v1.2M196.8 136.1v1.3h-1.9M196.8 136.1l-.3 .7M196.8 136.1l.4 .7M202.2 122.5v.6h.7l-.7 .7-.6-.7h.6"/>
<path d="M202.2 121.2h1.3M203.5 136.8v1.2h1.4M203.5 136.8l-.4 .6M203.5 136.8l.4 .6M205.9 138h1.4M207.6 138v.7h.7l-.7 .6-.6-.6h.6M208 139.3h1.9M208 138h1.9M209.9 137.4h1.2v5.1h-1.2zM209.9 138h.6v.1h-.6zM209.9 139.2h.6v.2h-.6zM212.4 121.2h1.3"/>
<path d="M221.9 121.2h2.6M221.9 122.5h2.6M231.1 136.5h1.4M233.4 121.2h2.5M233.4 122.5h2.5M233.4 123.8h2.5M233.6 136.5h3.3M234.9 136.5v.6h.7l-.7 .6-.6-.6h.6M234.9 137.7h2M234.9 139h2M236.9 135.8h1.2v3.8h-1.2zM236.9 138.9h.6v.2h-.6z"/>
<path d="M236.9 136.4h.6v.1h-.6zM236.9 137.7h.6v.1h-.6zM236.9 120.6l.5-.3-.5-.4-.6 .4 .6 .3v.6M236.9 121.2h.1M260.3 129.2h2l.3 .6-.3 .5h-2zM262.6 133v1.2h.6M262.6 137.4v1.3h.6M262.6 120.9h.6M262.6 125.3h.6M262.6 133l-.4 .6M262.6 133l.4 .6M262.6 137.4l-.4 .6"/>
<path d="M262.6 137.4l.4 .6M262.6 129.8h.6M263.2 120.4h2.5v1h-2.5zM263.2 124.8h2.5v1.1h-2.5zM263.2 133.7h2.5v1h-2.5zM263.2 138.2h2.5v1h-2.5zM263.2 129.3h2.5v1h-2.5zM265.7 138.7h4.5v.6h.6l-.6 .6-.6-.6h.6M265.7 120.9h4.5M265.7 125.3h4.5M265.7 134.2h4.5M265.7 129.8h4.5"/>
<path d="M267.7 120.3l1.2 .6-1.2 .6zM267.7 124.7l1.2 .6-1.2 .7zM267.7 133.6l1.2 .6-1.2 .7zM267.7 138l1.2 .7-1.2 .6zM267.7 129.2l1.2 .6-1.2 .6zM268.9 120.3v1.2M268.9 124.7v1.3M268.9 129.2v1.2M268.9 133.6v1.3M268.9 138v1.3M269.9 120.1v-.3h-.3h.3l-.7 .7M269.9 124.6v-.4h-.3h.3l-.7 .8"/>
<path d="M269.9 133.5v-.4h-.3h.3l-.7 .8M269.9 137.9v-.4h-.3h.3l-.7 .8M269.9 129v-.4h-.3h.3l-.7 .8M270.6 120.1v-.3h-.4h.4l-.8 .7M270.6 124.6v-.4h-.4h.4l-.8 .8M270.6 133.5v-.4h-.4h.4l-.8 .8M270.6 137.9v-.4h-.4h.4l-.8 .8M270.6 129v-.4h-.4h.4l-.8 .8M291 130.2h1M5 155.3h1M59.7 145h2.5M59.7 148.8h2.5"/>
<path d="M62.2 143.8h6.4v6.3h-6.4zM62.2 146.9h-2.5v.7h.6l-.6 .6-.6-.6h.6M66.7 145l-1.3 1.9M68.6 146.9h2.5v.7h.7l-.7 .6-.6-.6h.6M68.6 145h2.5M68.6 148.8h2.5M94.6 159.6v1.9M94.6 159.6l-.4 .7M94.6 159.6l.4 .7M99.1 159.6v1.9M99.1 159.6l-.4 .7M99.1 159.6l.3 .7"/>
<path d="M160.3 140.3h.7M160.3 144.1h.7M161 143.6h2.5v1h-2.5zM163.5 140.3h1.9M163.5 144.1h7M164.8 140.7h2.5v1h-2.5zM165.4 143.4l1.3 .7-1.3 .6zM166.7 140.3h3.8M166.7 143.4v1.3M167.7 143.3v-.4h-.4h.4l-.8 .8M168 142.2h2.5M168 141.2h2.5"/>
<path d="M168 143.1h2.5M168.3 143.3v-.4h-.3h.3l-.7 .8M176.8 142.2h2.6M176.8 141.2h2.6M176.8 140.3h2.6M176.8 143.1h2.6M176.8 144.1h2.6M181.3 159v-.6h-17.8v16.5h17.8v-3.8M186.7 143.8v1.2M187.9 143.4h.1v.4h-.1zM188 143.8v1.9h.6l-.6 .6-.7-.6h.7M190.1 142.4h.4v.2h-.4z"/>
<path d="M190.1 141.2h.4v.1h-.4zM190.5 141.2h1.3M190.5 142.5h1.3M208 140.6h1.9M208 141.9h1.9M209.9 141.8h.6v.1h-.6zM209.9 140.5h.6v.1h-.6zM256.5 151.1h1.3v2.5h-1.3zM256.5 157.4h1.3v2.6h-1.3zM257.2 152.9h.6v.1h-.6zM257.2 151.6h.6v.2h-.6zM257.2 159.3h.6v.1h-.6z"/>
<path d="M257.2 158h.6v.1h-.6zM257.8 151.7h1.9M257.8 153h1.9M257.8 158h1.9M257.8 159.3h1.9M261 150.4v1.4M261 152.8v1.4M261 156.8v1.4M261 159.2v1.4M270.5 151.1h1.3v2.5h-1.3zM270.5 157.4h1.3v2.6h-1.3zM271.1 152.9h.7v.1h-.7z"/>
<path d="M271.1 151.6h.7v.2h-.7zM271.1 159.3h.7v.1h-.7zM271.1 158h.7v.1h-.7zM271.8 151.7h1.9M271.8 153h1.9M271.8 158h1.9M271.8 159.3h1.9M275 150.4v1.4M275 152.8v1.4M275 156.8v1.4M275 159.2v1.4M291 155.3h1"/>
<path d="M93.1 167.9h.9M94 166.6v2.6M94.1 161.5h1v2.6h-1zM94.6 169.2v1.9h.6l-.6 .6-.6-.6h.6M94.6 164.1v.6M94.6 165.3v1.3M97.5 167.9h.9M98.4 166.6v2.6M98.6 161.5h1v2.6h-1zM99.1 169.2v1.9h.6l-.6 .6-.7-.6h.7M99.1 164.1v.6M99.1 165.3v1.3"/>
<path d="M110.5 161.5h.6M110.5 162.8h.6M110.5 164.1h.6M111.1 161h2.6v1h-2.6zM111.1 162.3h2.6v1h-2.6zM111.1 163.6h2.6v1h-2.6zM113.7 161.5h3.1M113.7 162.8h3.1M113.7 164.1h3.1M116.8 160.9h8.9v3.8h-8.9zM125.7 164.1h2.6v.6h.6l-.6 .6-.7-.6h.7M125.7 161.5h2.6"/>
<path d="M125.7 162.8h2.6M157.8 162.8h.6M157.8 164.1h.6M157.8 166.6h.6M157.8 169.2h.6M158.4 162.3h2.6v1h-2.6zM158.4 163.6h2.6v1h-2.6zM158.4 166.1h2.6v1h-2.6zM158.4 168.7h2.6v1h-2.6zM161 164.1h2.5M161 166.6h2.5M161 169.2h2.5"/>
<path d="M161.6 161.5h1.9M161.6 162.8h1.9M161.6 171.7h1.9M161.6 173h1.9M161.6 164.1v1.2h1.9M161.6 170.4h1.9M161.6 164.1l-.4 .6M161.6 164.1l.4 .6M163.5 167.9h-1.9v.6h.6l-.6 .7-.6-.7h.6M168.6 160.9h3.8l1.9-1.9h.6v.6h1.3l.6-.6h6.4v12.1h-14.6zM181.3 173h1.9M256.5 163.8h1.3v2.5h-1.3z"/>
<path d="M257.2 165.6h.6v.1h-.6zM257.2 164.3h.6v.2h-.6zM257.8 164.4h1.9M257.8 165.7h1.9M261 177.7v.7h.6l-.6 .6-.7-.6h.7M261 163.1v1.4M261 165.5v1.4M262.6 177.7v1.3h1.9M262.6 177.7l.4 .7M262.6 177.7l-.4 .7M265.7 178.4v1.2M265.7 179h3.9"/>
<path d="M267.7 172.7h1.9M267.7 173.9h1.9M267.7 177.7h1.9M269.6 172h1.2v2.6h-1.2zM269.6 173.9h.6v.1h-.6zM269.6 172.6h.6v.1h-.6zM269.6 177.1h1.2v2.5h-1.2zM269.6 178.9h.6v.2h-.6zM269.6 177.7h.6v.1h-.6zM270.5 163.8h1.3v2.5h-1.3zM271.1 165.6h.7v.1h-.7zM271.1 164.3h.7v.2h-.7z"/>
<path d="M271.8 164.4h1.9M271.8 165.7h1.9M275 163.1v1.4M275 165.5v1.4M5 180.2h1M237 188.2h54v16h-54zM237 199h54M237 196h54M242.3 196.3l-.7 1M249.1 198l-.1-.1-.2 .1 .1 .1 .2 .1v.2h-.3M249.8 198l-.2-.1-.1 .2v.3h.3M250.1 198h.3l.1 .4"/>
<path d="M250.1 197.7v.7M291 180.2h1M30 204.2v1M55 204.2v1M80 204.2v1M105 204.2v1M130 204.2v1M155 204.2v1M180 204.2v1M205 204.2v1M230 204.2v1M237 202.5h54"/>
<path d="M237 201h54M241.6 201.5l.2-.1 .2 .2-.5 .5h.5M247 201v1.5M253.4 203l.2-.2v.7M253.4 203.5h.4M254.2 203.5h.1M254.9 202.8h-.4v.3h.3l.1 .4h-.4M255 204.2v1M255.2 202.7a.85 .85 0 0 1 0 1.1M255.7 203.2h.6M256.6 202.8h.4l-.2 .3h.2v.4h-.4M268.3 205h.3"/>
<path d="M279 201v3.2M280 204.2v1M283.4 202.7l-.6 1M283.6 203l.2-.2v.7M283.6 203.5h.5"/>
<circle cx="42.2" cy="16.1" r=".25"/>
<circle cx="42.2" cy="18.7" r=".25"/>
<circle cx="44.2" cy="17.4" r=".25"/>
<circle cx="49.7" cy="17.4" r="1.4"/>
<circle cx="104.1" cy="19.9" r=".32"/>
<circle cx="96.5" cy="34.5" r=".32"/>
<circle cx="96.5" cy="21.2" r=".32"/>
<circle cx="104.1" cy="39.9" r=".32"/>
<circle cx="104.1" cy="26.6" r=".32"/>
<circle cx="104.1" cy="33.3" r=".32"/>
<circle cx="14.2" cy="56.4" r=".25"/>
<circle cx="14.6" cy="45.3" r=".44"/>
<circle cx="16.3" cy="56.4" r=".25"/>
<circle cx="17.1" cy="45.3" r=".44"/>
<circle cx="96.5" cy="49.1" r=".32"/>
<circle cx="104.1" cy="47.9" r=".32"/>
<circle cx="104.1" cy="54.5" r=".32"/>
<circle cx="96.5" cy="62.5" r=".32"/>
<circle cx="96.5" cy="77.1" r=".32"/>
<circle cx="104.1" cy="75.8" r=".32"/>
<circle cx="104.1" cy="67.9" r=".32"/>
<circle cx="104.1" cy="61.2" r=".32"/>
<circle cx="96.5" cy="90.4" r=".32"/>
<circle cx="104.1" cy="89.1" r=".32"/>
<circle cx="104.1" cy="82.5" r=".32"/>
<circle cx="104.1" cy="95.8" r=".32"/>
<circle cx="255.5" cy="97.4" r=".25"/>
<circle cx="255.5" cy="99.9" r=".25"/>
<circle cx="257.6" cy="98.7" r=".25"/>
<circle cx="263.1" cy="98.7" r="1.4"/>
<circle cx="271.7" cy="100.9" r="1.4"/>
<circle cx="277.2" cy="103.4" r=".44"/>
<circle cx="277.2" cy="100.9" r=".44"/>
<circle cx="65.1" cy="130.4" r="1.41"/>
<circle cx="65.4" cy="146.9" r="1.42"/>
<circle cx="94.6" cy="166.9" r=".25"/>
<circle cx="94.6" cy="168.9" r=".25"/>
<circle cx="99.1" cy="166.9" r=".25"/>
<circle cx="99.1" cy="168.9" r=".25"/>
</g>
<g fill="none" stroke="#840000" stroke-width=".25">
<path d="M20.9 10v2.1M21.7 10v2.1M26.6 20h2M26.6 19.2h2M30.4 19.4h2M30.4 18.6h2M53.3 19.4h2M53.3 18.6h2M65.3 19.4h2.1M65.3 18.6h2.1M121.9 15.6h2M121.9 14.8h2"/>
<path d="M144.1 12.4h2M144.1 11.6h2M161.2 19h2.1M161.2 18.3h2.1M196.8 12.4h2M196.8 11.6h2M213.9 19h2.1M213.9 18.3h2.1M11 21.3h2.1M11 20.5h2.1M13 36.2h2M13 35.4h2"/>
<path d="M15.2 32.6v1.3M17.1 32.6v1.3M17.4 36.2h2M17.4 35.4h2M33.3 33.6h2M33.3 32.9h2M37.7 33.6h2.1M37.7 32.9h2.1M42.2 33.6h2M42.2 32.9h2M46.6 33.6h2M46.6 32.9h2"/>
<path d="M51.1 33.6h2M51.1 32.9h2M55.5 33.6h2M55.5 32.9h2M121.9 34.9h2M121.9 34.2h2M144.1 30.5h2M144.1 29.7h2M161.2 37.1h2.1M161.2 36.4h2.1M196.8 30.5h2M196.8 29.7h2"/>
<path d="M213.9 37.1h2.1M213.9 36.4h2.1M14.9 59.2v2.1M15.6 59.2v2.1M29.5 50.5h2M29.5 49.7h2M121.9 54.3h2M121.9 53.5h2M144.1 52.1h2M144.1 51.3h2M161.2 58.7h2.1M161.2 58h2.1"/>
<path d="M196.8 52.1h2M196.8 51.3h2M213.9 58.7h2.1M213.9 58h2.1M121.9 73.7h2M121.9 72.9h2M144.1 70.2h2M144.1 69.4h2M161.2 76.8h2.1M161.2 76.1h2.1M196.8 70.2h2M196.8 69.4h2"/>
<path d="M213.9 76.8h2.1M213.9 76.1h2.1M260.6 67.6a1.63 1.63 0 0 1 2 0M260.6 66.5h2M265.7 67.6a1.63 1.63 0 0 1 2 0M265.7 66.5h2M270.4 67.3h2.1M270.4 66.5h2.1M274.9 67.3h2M274.9 66.5h2M144.1 91.8h2M144.1 91h2"/>
<path d="M161.2 98.4h2.1M161.2 97.7h2.1M196.8 91.8h2M196.8 91h2M213.9 98.4h2.1M213.9 97.7h2.1M63.1 102.4v2.1M63.9 102.4v2.1M144.1 109.8h2M144.1 109.1h2M161.2 116.5h2.1M161.2 115.8h2.1"/>
<path d="M196.8 109.8h2M196.8 109.1h2M213.9 116.5h2.1M213.9 115.8h2.1M32.6 132.9v2M33.3 127.8v3.3M33.4 132.9v2M34 127.8v3.3M64.8 129.5v1.9M154.9 138.1h2M154.9 137.3h2M205 137v2.1"/>
<path d="M205.8 137v2.1M232.7 135.4v2.1M233.4 135.4v2.1M260 152.7h2M260 151.9h2M260 159.1h2M260 158.3h2M273.9 152.7h2.1M273.9 151.9h2.1M273.9 159.1h2.1M273.9 158.3h2.1M260 165.4h2"/>
<path d="M260 164.6h2M273.9 165.4h2.1M273.9 164.6h2.1"/>
</g>
<g fill="#840000" stroke="#840000" stroke-width=".13">
<path d="M277.1 16.5l.9-.4a.72 .72 0 0 0 .6-.3l.2-.1a.37 .37 0 0 1 .5-.1 .83 .83 0 0 1 .8 .8l.1 .3a.37 .37 0 0 1 0 .7 2.83 2.83 0 0 0-.7 2.2 .36 .36 0 0 1 .1 .5 .58 .58 0 0 0 .2 .9 .59 .59 0 0 1 0 .8l-.1 .2a1.05 1.05 0 0 0 0 1.1l-.2 .3v.5a2.33 2.33 0 0 1-.4 2.1l-.1 .8-.2-.4v-.7a1.48 1.48 0 0 1 .1-1.3 .97 .97 0 0 1 .1-1l.1-1.1-.1-.7a1.19 1.19 0 0 1-.1-1.1v-.1a.98 .98 0 0 1-.2-1.2v-.1a.24 .24 0 0 1-.3-.3 .24 .24 0 0 1 .2-.2l.1-.1 .1-.9a.41 .41 0 0 0-.2-.7l-.4-.1-.6-.1-.4-.1z"/>
<path d="M269.7 16.3l1.3-.4a2.15 2.15 0 0 0 1.2-.3 1.21 1.21 0 0 0 1 .2 .39 .39 0 0 0 .6 0l2.1-.7 .7 .5a.34 .34 0 0 1 .3 .4l.2 .1-.3 .3a1.51 1.51 0 0 0-.3 1.6l.1 .9 .1 .1-.1 .3a1.79 1.79 0 0 0 .1 1.7 .62 .62 0 0 1-.4 .8l-.3 .8v1.2l-.1 1.5v.6l.2 .3a.73 .73 0 0 1-.2 .7v1l-.2 .4-.2 .2-.1-.4 .1-.2a.72 .72 0 0 0-.1-.9l-.2-.5v-1.7l-.1-.3v-.4l-.1-.3a3.7 3.7 0 0 1 .5-2l-.1-.6a3.5 3.5 0 0 1-.1-1.6 .54 .54 0 0 1-.1-.7l-.1-.7a.52 .52 0 0 0-.2-.8v-.1a.78 .78 0 0 0 0-.8l-.1-.1-.2-.2-.6-.1a.39 .39 0 0 0-.5 .2v.7l-.6 .2 .1 1.1a1.05 1.05 0 0 0-.1 1.3l.4 1.2-.2 .4 .1 .7a.89 .89 0 0 1 0 1.1 3 3 0 0 0-.1 1.7l-.1 1.3v1.1l-.3-.4-.2-1.4a1.82 1.82 0 0 1-.3-1.3 .54 .54 0 0 1 0-.9v-.1a1.76 1.76 0 0 0 0-1.4l-.1-.8-.2-.8a1.11 1.11 0 0 1-.1-1.4l.1-.5a1.04 1.04 0 0 0-.4-1l-.1-.3a.37 .37 0 0 0-.3-.4z"/>
<path d="M211.8 91.7l1.2 .6-1.2 .7z"/>
<path d="M211.8 109.8l1.2 .6-1.2 .7z"/>
<path d="M19 47.2h1.3l-.6 1.3z"/>
<path d="M211.8 12.3l1.2 .6-1.2 .7z"/>
<path d="M159.1 91.7l1.2 .6-1.2 .7z"/>
<path d="M159.1 109.8l1.2 .6-1.2 .7z"/>
<path d="M211.8 70.1l1.2 .6-1.2 .7z"/>
<path d="M211.8 30.4l1.2 .6-1.2 .7z"/>
<path d="M211.8 52l1.2 .6-1.2 .7z"/>
<path d="M264.5 178.4l1.2 .6-1.2 .6z"/>
<path d="M28.6 11l1.2-.6v1.3z"/>
<path d="M49.5 17.2l.5 .2-.5 .2z"/>
<path d="M262.9 98.5l.5 .2-.5 .2z"/>
<path d="M271.3 100.9l.5-.2v.4z"/>
<path d="M268 96.1l1.2-.6v1.3z"/>
<path d="M65.1 131.3l.2-.2 .3 .5z"/>
<path d="M61.9 126l1.3 .6-1.3 .6z"/>
<path d="M187.7 139.3h.4v.4h-.4z"/>
<path d="M188.3 138.6l.6 .3-.6 .3z"/>
<path d="M185.8 137.2h1.3l-.2 .3h-1z"/>
<path d="M193.7 136.8l1.2 .6-1.2 .6z"/>
<path d="M169.2 170.1h1.3v.6h-1.3z"/>
<path d="M169.2 168.8h1.3v.7h-1.3z"/>
<path d="M169.2 167.6h1.3v.6h-1.3z"/>
<path d="M169.2 166.3h1.3v.6h-1.3z"/>
<path d="M169.2 165h1.3v.7h-1.3z"/>
<path d="M169.2 163.8h1.3v.6h-1.3z"/>
<path d="M169.2 162.5h1.3v.6h-1.3z"/>
<path d="M169.2 161.2h1.3v.7h-1.3z"/>
<path d="M159.1 70.1l1.2 .6-1.2 .7z"/>
<path d="M159.1 52l1.2 .6-1.2 .7z"/>
<path d="M159.1 12.3l1.2 .6-1.2 .7z"/>
<path d="M33.3 15.8l1.3 .6-1.3 .7z"/>
<path d="M268.6 74.5l1.3 .7-1.3 .6z"/>
<path d="M159.1 30.4l1.2 .6-1.2 .7z"/>
<circle cx="50.2" cy="18.3" r=".13"/>
<circle cx="50.2" cy="16.5" r=".13"/>
<circle cx="263.5" cy="99.6" r=".13"/>
<circle cx="263.5" cy="97.8" r=".13"/>
<circle cx="272.1" cy="101.8" r=".13"/>
<circle cx="272.1" cy="100" r=".13"/>
<circle cx="186.1" cy="138.9" r=".32"/>
<circle cx="187.6" cy="138.2" r=".19"/>
</g>
<g fill="#ffffc2" stroke="#ffffc2" stroke-width=".13">
<path d="M203.5 94.2h8.9v10.2h-8.9z"/>
<path d="M203.5 112.3h8.9v10.2h-8.9z"/>
<path d="M26.4 101.5h1.2v12.7h-1.2z"/>
<path d="M8.9 43.4h1.3v7.6h-1.3z"/>
<path d="M36.2 101.5h2.5v12.7h-2.5z"/>
<path d="M67.9 102.8h1.3v5.1h-1.3z"/>
<path d="M270.5 151.1h1.3v2.5h-1.3z"/>
<path d="M256.5 151.1h1.3v2.5h-1.3z"/>
<path d="M256.5 157.4h1.3v2.6h-1.3z"/>
<path d="M270.5 157.4h1.3v2.6h-1.3z"/>
<path d="M256.5 163.8h1.3v2.5h-1.3z"/>
<path d="M270.5 163.8h1.3v2.5h-1.3z"/>
<path d="M203.5 14.9h8.9v10.1h-8.9z"/>
<path d="M150.8 94.2h8.9v10.2h-8.9z"/>
<path d="M150.8 112.3h8.9v10.2h-8.9z"/>
<path d="M203.5 72.6h8.9v10.2h-8.9z"/>
<path d="M203.5 33h8.9v10.1h-8.9z"/>
<path d="M203.5 54.5h8.9v10.2h-8.9z"/>
<path d="M92.4 19.3l3.8 1.9-3.8 1.9z"/>
<path d="M92.4 32.6l3.8 1.9-3.8 1.9z"/>
<path d="M92.4 47.2l3.8 1.9-3.8 1.9z"/>
<path d="M92.4 60.6l3.8 1.9-3.8 1.9z"/>
<path d="M92.4 75.2l3.8 1.9-3.8 1.9z"/>
<path d="M92.4 88.5l3.8 1.9-3.8 1.9z"/>
<path d="M127 15.8h5.1v7.6h-5.1z"/>
<path d="M101.6 24.7a2.62 2.62 0 0 1 2.2 1.9l-2.5 .7z"/>
<path d="M101.3 25.9l2.5 .7a2.6 2.6 0 0 1-2.2 1.9z"/>
<path d="M100 28.5h1.6z"/>
<path d="M100 24.7h1.6z"/>
<path d="M100 24.7h1.6v3.8h-1.6a3.3 3.3 0 0 0 0-3.8z"/>
<path d="M101.6 31.4a2.62 2.62 0 0 1 2.2 1.9l-2.5 .6z"/>
<path d="M101.3 32.6l2.5 .7a2.6 2.6 0 0 1-2.2 1.9z"/>
<path d="M100 35.2h1.6z"/>
<path d="M100 31.4h1.6z"/>
<path d="M100 31.4h1.6v3.8h-1.6a3.3 3.3 0 0 0 0-3.8z"/>
<path d="M101.6 38a2.62 2.62 0 0 1 2.2 1.9l-2.5 .7z"/>
<path d="M101.3 39.3l2.5 .6a2.6 2.6 0 0 1-2.2 2z"/>
<path d="M100 41.8h1.6z"/>
<path d="M100 38h1.6z"/>
<path d="M100 38h1.6v3.8h-1.6a3.3 3.3 0 0 0 0-3.8z"/>
<path d="M101.6 18a2.62 2.62 0 0 1 2.2 1.9l-2.5 .7z"/>
<path d="M101.3 19.3l2.5 .6a2.6 2.6 0 0 1-2.2 2z"/>
<path d="M100 21.8h1.6z"/>
<path d="M100 18h1.6z"/>
<path d="M100 18h1.6v3.8h-1.6a3.3 3.3 0 0 0 0-3.8z"/>
<path d="M127 35.2h5.1v7.6h-5.1z"/>
<path d="M101.6 52.6a2.62 2.62 0 0 1 2.2 1.9l-2.5 .7z"/>
<path d="M101.3 53.9l2.5 .7a2.6 2.6 0 0 1-2.2 1.9z"/>
<path d="M100 56.4h1.6z"/>
<path d="M100 52.6h1.6z"/>
<path d="M100 52.6h1.6v3.8h-1.6a3.3 3.3 0 0 0 0-3.8z"/>
<path d="M101.6 59.3a2.62 2.62 0 0 1 2.2 1.9l-2.5 .7z"/>
<path d="M101.3 60.5l2.5 .7a2.6 2.6 0 0 1-2.2 1.9z"/>
<path d="M100 63.1h1.6z"/>
<path d="M100 59.3h1.6z"/>
<path d="M100 59.3h1.6v3.8h-1.6a3.3 3.3 0 0 0 0-3.8z"/>
<path d="M236.9 135.8h1.2v3.8h-1.2z"/>
<path d="M269.6 172h1.2v2.6h-1.2z"/>
<path d="M269.6 177.1h1.2v2.5h-1.2z"/>
<path d="M127 73.9h5.1v7.6h-5.1z"/>
<path d="M101.6 66a2.62 2.62 0 0 1 2.2 1.9l-2.5 .6z"/>
<path d="M101.3 67.2l2.5 .7a2.6 2.6 0 0 1-2.2 1.9z"/>
<path d="M100 69.8h1.6z"/>
<path d="M100 66h1.6z"/>
<path d="M100 66h1.6v3.8h-1.6a3.3 3.3 0 0 0 0-3.8z"/>
<path d="M101.6 46a2.62 2.62 0 0 1 2.2 1.9l-2.5 .6z"/>
<path d="M101.3 47.2l2.5 .7a2.6 2.6 0 0 1-2.2 1.9z"/>
<path d="M100 49.8h1.6z"/>
<path d="M100 46h1.6z"/>
<path d="M100 46h1.6v3.8h-1.6a3.3 3.3 0 0 0 0-3.8z"/>
<path d="M101.6 80.6a2.62 2.62 0 0 1 2.2 1.9l-2.5 .6z"/>
<path d="M101.3 81.8l2.5 .7a2.6 2.6 0 0 1-2.2 1.9z"/>
<path d="M100 84.4h1.6z"/>
<path d="M100 80.6h1.6z"/>
<path d="M100 80.6h1.6v3.8h-1.6a3.3 3.3 0 0 0 0-3.8z"/>
<path d="M101.6 87.2a2.62 2.62 0 0 1 2.2 1.9l-2.5 .7z"/>
<path d="M101.3 88.5l2.5 .7a2.6 2.6 0 0 1-2.2 1.9z"/>
<path d="M100 91.1h1.6z"/>
<path d="M100 87.2h1.6z"/>
<path d="M100 87.2h1.6v3.9h-1.6a3.3 3.3 0 0 0 0-3.9z"/>
<path d="M101.6 93.9a2.62 2.62 0 0 1 2.2 1.9l-2.5 .7z"/>
<path d="M101.3 95.2l2.5 .6a2.6 2.6 0 0 1-2.2 1.9z"/>
<path d="M100 97.7h1.6z"/>
<path d="M100 93.9h1.6z"/>
<path d="M100 93.9h1.6v3.8h-1.6a3.3 3.3 0 0 0 0-3.8z"/>
<path d="M101.6 73.9a2.62 2.62 0 0 1 2.2 1.9l-2.5 .7z"/>
<path d="M101.3 75.2l2.5 .6a2.6 2.6 0 0 1-2.2 1.9z"/>
<path d="M100 77.7h1.6z"/>
<path d="M100 73.9h1.6z"/>
<path d="M100 73.9h1.6v3.8h-1.6a3.3 3.3 0 0 0 0-3.8z"/>
<path d="M127 54.5h5.1v7.7h-5.1z"/>
<path d="M170.5 137.7h6.3v7h-6.3z"/>
<path d="M209.9 137.4h1.2v5.1h-1.2z"/>
<path d="M185.4 136.1h5.1v7.7h-5.1z"/>
<path d="M168.6 160.9h3.8l1.9-1.9h.6v.6h1.3l.6-.6h6.4v12.1h-14.6z"/>
<path d="M150.8 72.6h8.9v10.2h-8.9z"/>
<path d="M273.7 30.7h1.3v2.6h-1.3z"/>
<path d="M150.8 54.5h8.9v10.2h-8.9z"/>
<path d="M57.1 15.2h6.4v4.4h-6.4z"/>
<path d="M150.8 14.9h8.9v10.1h-8.9z"/>
<path d="M150.8 33h8.9v10.1h-8.9z"/>
<path d="M34 41.8h15.2v42h-15.2z"/>
</g>
<path d="M15.6 32h1.2v2.5h-1.2z" fill="none" stroke="#840000" stroke-width=".15"/>
<g fill="none" stroke="#008484" stroke-width=".13">
<path d="M36.3 77.7h.3M266.8 78.4h.4l-.2 .2 .1 .1 .1 .2-.1 .1-.3-.1M270 78.4h.3l.1 .1-.4 .5h.4M264.2 85.5l.3 .8 .2-.8M272.5 85.7l.2-.2v.8M272.5 86.3h.4M40.6 137.4h.4M161.4 137.5h.4l-.2 .3h.2v.3h-.4M175 139.9a.32 .32 0 0 1 .4 .3 .32 .32 0 0 1-.4 .3zM175.7 140.3h.4M186.3 140.4h.7M186.6 140.4v.2l.1 .1h.2v-.3"/>
<path d="M188.7 140.9a.32 .32 0 0 1 .3 .3 .32 .32 0 0 1-.3 .3zM189.3 141.3h.5M167.8 162.5a.32 .32 0 0 1 .3 .3 .32 .32 0 0 1-.3 .3z"/>
</g>
<path d="M137.8 47.6h105.4M137.8 86.9h105.4M137.8 126.6v-120.3M137.8 126.6h105.4M190.5 126.6v-120.3M243.2 126.6v-120.3" fill="none" stroke="#0000c2" stroke-width=".13" stroke-dasharray=".2 .2"/>
<g fill="none" stroke="#008400" stroke-width=".13">
<path d="M8.6 19h7.6M16.2 17.7h-8.9v5.1h1.3M19.4 11h-3.2v5.4M23.2 11h3.5v5.4M26.4 16.4h.6M28.3 17.7h-1.9v1.3M29.5 16.4h1.9v.7M29.8 15.8v.6M36.5 15.5v.9M39.4 16.1h1.2M45.4 12h.6v1.6M45.7 17.4h.7"/>
<path d="M49.8 19.9h.4M54.6 16.4h-.3v.7M66 16.4h.4v.7M89.2 18.7h8.9M97.5 18.7v6.6h.6M157.2 12.3v.6M161 18.7h4.4v1.2M161 16.1h1.2M162.2 12.9v3.9M183.2 17.4v5.1M209.9 12.3v.6M213.7 16.1h1.2"/>
<path d="M213.7 18.7h4.4v1.2M214.9 12.9v3.9M235.9 17.4v5.1M12.1 22.8h4.7M13.3 33.3h1M14 33.3v.6M14 37.7h4.4M18.1 33.3h.9M18.4 33.3v.6M31.4 20.9v.6h-3.8M34.3 35.2h22.2M34.3 31.4h22.2"/>
<path d="M54.3 20.9v1.3h12.1v-1.3M89.2 21.2h1.3M89.2 34.5h1.3M89.2 32h8.9M89.9 21.2v6.7h8.2M89.9 34.5v6.7h8.2M97.5 32v6.7h.6M141.9 39.3h7.6M142.2 21.2h7.3M149.5 23.7v1.3M157.2 30.4v.6M161 34.2h1.2"/>
<path d="M161 36.8h4.4v1.2M162.2 20.6v.6h-1.2M162.2 31v3.9M162.2 38.7v.6h-1.2M165.4 22.5v1.2h-4.4M169.2 23.7v1.3M183.2 35.5v5.1M185.1 23.7h-1.9v2.6M194.6 21.2h7.6M194.6 39.3h7.6M202.2 23.7v1.3M209.9 30.4v.6"/>
<path d="M213.7 34.2h1.2M213.7 36.8h4.4v1.2M214.9 20.6v.6h-1.2M214.9 38.7v.6h-1.2M214.9 31v3.9M218.1 22.5v1.2h-4.4M221.9 23.7v1.3M235.9 35.5v5.1M237.8 23.7h-1.9v2.6M269.6 32.6h2.2M270.8 31.4h1M12.1 49.1h1.6"/>
<path d="M12.1 44.1h.3M12.1 47.9h1.6M12.1 46.6h1.6M12.7 56.4v3.9h.6M17.8 56.4v3.9h-.7M19.7 50.4h3.8M27.6 49.5v2.5h2.9M27.6 45.7h5.1M30.5 48.2h2.2M39.1 40.6h6.3M89.2 49.1h1.3M89.2 46.6h8.9"/>
<path d="M89.2 59.9h8.9M89.9 49.1v6.7h8.2M97.5 46.6v6.7h.6M97.5 59.9v6.7h.6M149.5 41.8v1.3M157.2 52v.6M161 58.4h4.4v1.2M161 55.8h1.2M162.2 52.6v3.8M165.4 40.6v1.2h-4.4M169.2 41.8v1.3M183.2 57.1v5.1"/>
<path d="M185.1 41.8h-1.9v2.6M202.2 41.8v1.3M209.9 52v.6M213.7 55.8h1.2M213.7 58.4h4.4v1.2M214.9 52.6v3.8M218.1 40.6v1.2h-4.4M221.9 41.8v1.3M235.9 57.1v5.1M237.8 41.8h-1.9v2.6M89.2 62.5h1.3M89.2 74.5h8.9"/>
<path d="M89.2 77.1h1.3M89.9 62.5v6.6h8.2M89.9 77.1v6.7h8.2M97.5 74.5v6.7h.6M141.9 60.9h7.6M141.9 79h7.6M149.5 63.4v1.3M157.2 70.1v.6M161 76.4h4.4v1.3M161 73.9h1.2M162.2 60.3v.6h-1.2M162.2 70.7v3.8"/>
<path d="M162.2 78.4v.6h-1.2M165.4 62.2v1.2h-4.4M169.2 63.4v1.3M183.2 75.2v5.1M185.1 63.4h-1.9v2.6M194.6 60.9h7.6M194.6 79h7.6M202.2 63.4v1.3M209.9 70.1v.6M213.7 76.4h4.4v1.3M213.7 73.9h1.2M214.9 60.3v.6h-1.2"/>
<path d="M214.9 78.4v.6h-1.2M214.9 70.7v3.8M218.1 62.2v1.2h-4.4M221.9 63.4v1.3M235.9 75.2v5.1M237.8 63.4h-1.9v2.6M261.6 65h14.3M261.6 68.8h14.3M271.8 75.2h.6M39.1 85h5M89.2 87.9h8.9M89.2 90.4h1.3"/>
<path d="M89.9 90.4v6.7h8.2M97.5 87.9v6.6h.6M149.5 81.5v1.3M157.2 91.7v.6M161 98h4.4v1.3M161 95.5h1.2M162.2 92.3v3.8M162.2 99.9v.7h-1.2M165.4 80.3v1.2h-4.4M169.2 81.5v1.3M183.2 96.8v5M185.1 81.5h-1.9v2.6"/>
<path d="M202.2 81.5v1.3M209.9 91.7v.6M213.7 98h4.4v1.3M213.7 95.5h1.2M214.9 99.9v.7h-1.2M214.9 92.3v3.8M218.1 80.3v1.2h-4.4M221.9 81.5v1.3M235.9 96.8v5M237.8 81.5h-1.9v2.6M253.4 94.2h6v.3M259.1 98.7h.6"/>
<path d="M259.4 98.4v.3M261 89.5h2.5M263.5 80.9v-1.9h10.2v1.9M263.5 92v4.1h2.6M263.5 82.2v1.9h10.2M271.1 96.1h3.5M272.1 98.4h5.1M273.7 82.2v6M273.7 92h.9v6.4M34.3 102.2v11.4M40.6 102.2v11.4M55.6 107.2h10.4"/>
<path d="M58.7 106h7.3M58.7 102.2h-3.1v1.2M59.4 111.4h5.7M59.4 111.1v.6M61.6 103.4v1.3h4.4M62.9 110.1h.6M62.9 109.8v.6M65.4 103.4h.6M141.9 100.6h7.6M141.9 118.7h7.6M149.5 103.1v1.3M157.2 109.8v.6"/>
<path d="M161 116.1h4.4v1.3M161 113.6h1.2M162.2 110.4v3.8M162.2 118v.7h-1.2M165.4 101.8v1.3h-4.4M165.4 119.9v1.3h-4.4M169.2 103.1v1.3M183.2 114.9v5M185.1 103.1h-1.9v2.6M194.6 100.6h7.6M194.6 118.7h7.6M202.2 103.1v1.3"/>
<path d="M209.9 109.8v.6M213.7 116.1h4.4v1.3M213.7 113.6h1.2M214.9 118v.7h-1.2M214.9 110.4v3.8M218.1 101.8v1.3h-4.4M218.1 119.9v1.3h-4.4M221.9 103.1v1.3M235.9 114.9v5M237.8 103.1h-1.9v2.6M262.9 101.2h.6M267.7 100.9h.6"/>
<path d="M268.3 104.7h3.8M270.2 116.5v22.2M272.1 103.4v2.6h5.1M24.8 136.5h10.8M28.3 128.8v2.6M28.3 135.2h7.3M31.1 128.8v8.9h4.5M31.1 132.6h4.5M31.7 130.1v1.3h3.9M31.7 128.8h-6.9v3.8M34.9 133.9h.7M60 126.6v1.3h5.7"/>
<path d="M65.1 126.6h.6M149.5 121.2v1.3M168 138.4h-7.7v5.7M169.2 121.2v1.3M179.4 138.4h4.7M185.1 121.2h-1.9v2.6M202.2 121.2v1.3M203.5 138v1.3h4.5M207.3 138h.7M221.9 121.2v1.3M230.5 136.5h.6v1.2h3.8M230.5 139h4.4"/>
<path d="M237.8 121.2h-1.9v2.6M160.3 141.2h3.8M179.4 141.2h2.5M259.7 153v1.2h2.2M259.7 159.3v1.3h2.2M261.9 150.4h-2.2v1.3M261.9 156.8h-2.2v1.2M273.7 153v1.2h2.2M273.7 159.3v1.3h2.2M275.9 150.4h-2.2v1.3M275.9 156.8h-2.2v1.2M94.6 165h1"/>
<path d="M94.6 164.7v.6M99.1 165h.9M99.1 164.7v.6M128.3 161.5v2.6M259.7 165.7v1.2h2.2M261 177.7h6.7M261.9 163.1h-2.2v1.3M273.7 165.7v1.2h2.2M275.9 163.1h-2.2v1.3"/>
</g>
<g fill="none" stroke="#000" stroke-width=".13">
<path d="M29.9 17.1h.3M30 16.9v.6h.2M112 19.8v-.7l.2 .5 .2-.5v.7M112 33.1v-.6l.2 .4 .2-.4v.6M112.1 26.4v-.6l.2 .5 .2-.5v.6M112.1 39.8v-.7l.2 .5 .2-.5v.7M189 22.9v.7h.3M241.7 22.9v.7h.3M55.7 53.1v-.6l.3 .4 .2-.4v.6M55.7 54.4v-.7l.3 .5 .2-.5v.7M55.7 55.6v-.6l.3 .5 .2-.5v.6M55.7 56.9v-.6l.3 .4 .2-.4v.6"/>
<path d="M112 47.7v-.6l.2 .4 .2-.4v.6M112.1 54.4v-.7l.2 .5 .2-.5v.7M189 41.4l.3-.1v-.2l-.3-.1v.7M189.2 41.4l.2 .3M241.7 41.4l.3-.1v-.2l-.3-.1v.7M241.9 41.4l.2 .3M55 74.1l.1 .6 .1-.5 .1 .5 .2-.6M55 75.3l.1 .7 .1-.5 .1 .5 .2-.7M55.7 73.4v-.6l.3 .4 .2-.4v.6M55.7 72.2v-.7l.3 .5 .2-.5v.7M112 75.6v-.6l.2 .5 .2-.5v.6M112 61v-.6l.2 .5 .2-.5v.6"/>
<path d="M112.1 67.7v-.6l.2 .4 .2-.4v.6M189 62.6v.7h.3M241.7 62.6v.7h.3M274.1 74.6h.2M274.2 74.4v.5l.1 .1M112 89v-.7l.2 .5 .2-.5v.7M112.1 95.7v-.7l.2 .5 .2-.5v.7M112.1 82.3v-.6l.2 .4 .2-.4v.6M189 81.1l.3-.1v-.2l-.3-.1v.7M189.2 81.1l.2 .3M241.7 81.1l.3-.1v-.2l-.3-.1v.7M241.9 81.1l.2 .3"/>
<path d="M189 102.3v.7h.3M241.7 102.3v.7h.3M179.6 139.5a.32 .32 0 0 1 .3 .3 .32 .32 0 0 1-.3 .3zM180.2 139.9h.5M189 120.7h.3v-.2l-.3-.1v.7M189.2 120.7l.2 .4M241.7 120.7h.3v-.2l-.3-.1v.7M241.9 120.7l.2 .4M192.6 140.8h.5M265.8 156v.6h.3M265.8 149.6v.7h.3M265.8 153.8l.3-.1 .1-.2-.4-.1v.7"/>
<path d="M266 153.8l.2 .3M279.8 156v.6h.3M279.8 153.8l.3-.1v-.2l-.3-.1v.7M279.8 149.6v.7h.3M280 153.8l.2 .3M265.8 160.1h.3l.1-.3h-.4v.6M265.8 166.5l.3-.1 .1-.2-.4-.1v.7M265.8 162.3v.7h.3M266 160.1l.2 .3M266 166.5l.2 .3M279.8 160.1h.3v-.3h-.3v.6M279.8 166.5l.3-.1v-.2l-.3-.1v.7"/>
<path d="M279.8 162.3v.7h.3M280 160.1l.2 .3M280 166.5l.2 .3"/>
</g>
<g fill="none" stroke="#0000c2" stroke-width=".13">
<path d="M55.3 57.9h.3M55.7 57.6h-.4v.6h.4M55.9 58.2v-.6l.2 .4 .2-.4v.6M57 57.6a.29 .29 0 0 0-.4 .3 .29 .29 0 0 0 .4 .2v-.2h-.1M59.6 50.1l.2-.2v.7M59.6 51.3l.3-.1 .1 .2-.4 .4h.4M59.6 50.6h.4M61.2 43.6h.2l.2 .2-.4 .4h.4M62.2 52.6l.1-.1v.6M62.2 53.1h.3M62.3 56.3l-.1 .4h.3M62.5 56.5v.4"/>
<path d="M21.8 70.6l.2-.1 .1-.2h-.3v.6h.2l.1-.2-.1-.1M22.4 70.5v.4M22.6 70.5l-.2 .1M22.8 70.5h.2l.1 .4M23.1 70.6l-.3 .1v.2h.3M23.4 70.3v.6M23.4 70.6l.2 .3M23.6 70.5l-.2 .2M23.9 70.7l.3-.1-.1-.1h-.1l-.1 .1v.3h.2M60.9 61.5l.2-.1v.6M60.9 62h.4M62.2 72.9l.2-.1 .1 .2-.4 .4h.4"/>
<path d="M62.2 71.7l.1-.2v.7M62.2 72.2h.3"/>
</g>
<g fill="#008400" stroke="#008400" stroke-width=".13">
<circle cx="40.3" cy="40.6" r=".25"/>
<circle cx="128.3" cy="164.1" r=".25"/>
<circle cx="128.3" cy="162.8" r=".25"/>
<circle cx="39.1" cy="40.6" r=".25"/>
<circle cx="41.6" cy="40.6" r=".25"/>
<circle cx="42.9" cy="40.6" r=".25"/>
<circle cx="263.5" cy="96.1" r=".25"/>
<circle cx="162.2" cy="73.9" r=".25"/>
<circle cx="52.1" cy="31.4" r=".25"/>
<circle cx="97.5" cy="59.9" r=".25"/>
<circle cx="97.5" cy="74.5" r=".25"/>
<circle cx="183.2" cy="81.5" r=".25"/>
<circle cx="97.5" cy="87.9" r=".25"/>
<circle cx="47.6" cy="35.2" r=".25"/>
<circle cx="97.5" cy="32" r=".25"/>
<circle cx="184.1" cy="103.1" r=".25"/>
<circle cx="97.5" cy="18.7" r=".25"/>
<circle cx="43.2" cy="35.2" r=".25"/>
<circle cx="183.2" cy="77.7" r=".25"/>
<circle cx="38.7" cy="35.2" r=".25"/>
<circle cx="162.2" cy="113.6" r=".25"/>
<circle cx="89.9" cy="49.1" r=".25"/>
<circle cx="47.6" cy="31.4" r=".25"/>
<circle cx="89.9" cy="90.4" r=".25"/>
<circle cx="183.2" cy="103.1" r=".25"/>
<circle cx="43.2" cy="31.4" r=".25"/>
<circle cx="183.2" cy="104.4" r=".25"/>
<circle cx="55.6" cy="102.2" r=".25"/>
<circle cx="38.7" cy="31.4" r=".25"/>
<circle cx="34.3" cy="31.4" r=".25"/>
<circle cx="89.9" cy="77.1" r=".25"/>
<circle cx="184.1" cy="81.5" r=".25"/>
<circle cx="89.9" cy="62.5" r=".25"/>
<circle cx="183.2" cy="98" r=".25"/>
<circle cx="271.5" cy="65" r=".25"/>
<circle cx="270.2" cy="129.8" r=".25"/>
<circle cx="40.3" cy="85" r=".25"/>
<circle cx="270.2" cy="125.3" r=".25"/>
<circle cx="44.1" cy="40.6" r=".25"/>
<circle cx="44.1" cy="85" r=".25"/>
<circle cx="26.7" cy="11" r=".25"/>
<circle cx="160.3" cy="138.4" r=".25"/>
<circle cx="162.2" cy="95.5" r=".25"/>
<circle cx="56.5" cy="35.2" r=".25"/>
<circle cx="183.2" cy="82.8" r=".25"/>
<circle cx="89.9" cy="21.2" r=".25"/>
<circle cx="266.7" cy="65" r=".25"/>
<circle cx="183.2" cy="122.5" r=".25"/>
<circle cx="183.2" cy="121.2" r=".25"/>
<circle cx="183.2" cy="99.3" r=".25"/>
<circle cx="89.9" cy="34.5" r=".25"/>
<circle cx="184.1" cy="121.2" r=".25"/>
<circle cx="183.2" cy="76.4" r=".25"/>
<circle cx="97.5" cy="46.6" r=".25"/>
<circle cx="52.1" cy="35.2" r=".25"/>
<circle cx="183.2" cy="117.4" r=".25"/>
<circle cx="183.2" cy="116.1" r=".25"/>
<circle cx="235.9" cy="103.1" r=".25"/>
<circle cx="214.9" cy="95.5" r=".25"/>
<circle cx="59.4" cy="107.2" r=".25"/>
<circle cx="235.9" cy="98" r=".25"/>
<circle cx="235.9" cy="99.3" r=".25"/>
<circle cx="183.2" cy="18.7" r=".25"/>
<circle cx="183.2" cy="19.9" r=".25"/>
<circle cx="99.1" cy="165" r=".25"/>
<circle cx="94.6" cy="165" r=".25"/>
<circle cx="236.9" cy="103.1" r=".25"/>
<circle cx="62.9" cy="106" r=".25"/>
<circle cx="235.9" cy="104.4" r=".25"/>
<circle cx="184.1" cy="23.7" r=".25"/>
<circle cx="65.7" cy="103.4" r=".25"/>
<circle cx="61.6" cy="103.4" r=".25"/>
<circle cx="183.2" cy="23.7" r=".25"/>
<circle cx="183.2" cy="25" r=".25"/>
<circle cx="40.6" cy="112.3" r=".25"/>
<circle cx="40.6" cy="111.1" r=".25"/>
<circle cx="40.6" cy="109.8" r=".25"/>
<circle cx="274.6" cy="98.4" r=".25"/>
<circle cx="214.9" cy="16.1" r=".25"/>
<circle cx="274.6" cy="96.1" r=".25"/>
<circle cx="236.9" cy="81.5" r=".25"/>
<circle cx="235.9" cy="81.5" r=".25"/>
<circle cx="272.1" cy="104.7" r=".25"/>
<circle cx="235.9" cy="82.8" r=".25"/>
<circle cx="268.3" cy="100.9" r=".25"/>
<circle cx="259.4" cy="98.7" r=".25"/>
<circle cx="162.2" cy="16.1" r=".25"/>
<circle cx="162.2" cy="55.8" r=".25"/>
<circle cx="40.6" cy="108.5" r=".25"/>
<circle cx="277.2" cy="106" r=".25"/>
<circle cx="275" cy="156.8" r=".25"/>
<circle cx="275" cy="160.6" r=".25"/>
<circle cx="261" cy="156.8" r=".25"/>
<circle cx="261" cy="160.6" r=".25"/>
<circle cx="261" cy="163.1" r=".25"/>
<circle cx="261" cy="166.9" r=".25"/>
<circle cx="275" cy="166.9" r=".25"/>
<circle cx="275" cy="163.1" r=".25"/>
<circle cx="271.5" cy="68.8" r=".25"/>
<circle cx="16.2" cy="37.7" r=".25"/>
<circle cx="18.4" cy="33.3" r=".25"/>
<circle cx="14" cy="33.3" r=".25"/>
<circle cx="275" cy="154.2" r=".25"/>
<circle cx="275" cy="150.4" r=".25"/>
<circle cx="183.2" cy="43.1" r=".25"/>
<circle cx="183.2" cy="41.8" r=".25"/>
<circle cx="184.1" cy="41.8" r=".25"/>
<circle cx="275.9" cy="68.8" r=".25"/>
<circle cx="266.7" cy="68.8" r=".25"/>
<circle cx="235.9" cy="122.5" r=".25"/>
<circle cx="261" cy="154.2" r=".25"/>
<circle cx="261" cy="150.4" r=".25"/>
<circle cx="183.2" cy="38" r=".25"/>
<circle cx="183.2" cy="36.8" r=".25"/>
<circle cx="162.2" cy="34.2" r=".25"/>
<circle cx="270.2" cy="138.7" r=".25"/>
<circle cx="270.2" cy="134.2" r=".25"/>
<circle cx="270.2" cy="120.9" r=".25"/>
<circle cx="34.3" cy="107.2" r=".25"/>
<circle cx="40.6" cy="107.2" r=".25"/>
<circle cx="40.6" cy="106" r=".25"/>
<circle cx="40.6" cy="104.7" r=".25"/>
<circle cx="40.6" cy="103.4" r=".25"/>
<circle cx="40.6" cy="113.6" r=".25"/>
<circle cx="34.3" cy="112.3" r=".25"/>
<circle cx="34.3" cy="111.1" r=".25"/>
<circle cx="34.3" cy="109.8" r=".25"/>
<circle cx="214.9" cy="113.6" r=".25"/>
<circle cx="34.3" cy="108.5" r=".25"/>
<circle cx="34.3" cy="106" r=".25"/>
<circle cx="34.3" cy="104.7" r=".25"/>
<circle cx="34.3" cy="103.4" r=".25"/>
<circle cx="34.3" cy="102.2" r=".25"/>
<circle cx="235.9" cy="116.1" r=".25"/>
<circle cx="235.9" cy="117.4" r=".25"/>
<circle cx="236.9" cy="121.2" r=".25"/>
<circle cx="235.9" cy="121.2" r=".25"/>
<circle cx="27.6" cy="17.7" r=".25"/>
<circle cx="31.1" cy="132.6" r=".25"/>
<circle cx="235.9" cy="36.8" r=".25"/>
<circle cx="31.1" cy="133.9" r=".25"/>
<circle cx="235.9" cy="38" r=".25"/>
<circle cx="271.8" cy="75.2" r=".25"/>
<circle cx="236.9" cy="41.8" r=".25"/>
<circle cx="235.9" cy="41.8" r=".25"/>
<circle cx="235.9" cy="43.1" r=".25"/>
<circle cx="31.1" cy="128.8" r=".25"/>
<circle cx="26.4" cy="17.7" r=".25"/>
<circle cx="65.4" cy="126.6" r=".25"/>
<circle cx="65.7" cy="127.9" r=".25"/>
<circle cx="46" cy="17.4" r=".25"/>
<circle cx="183.2" cy="64.7" r=".25"/>
<circle cx="26.7" cy="16.4" r=".25"/>
<circle cx="235.9" cy="77.7" r=".25"/>
<circle cx="207.6" cy="138" r=".25"/>
<circle cx="203.5" cy="138" r=".25"/>
<circle cx="235.9" cy="25" r=".25"/>
<circle cx="41.6" cy="85" r=".25"/>
<circle cx="42.9" cy="85" r=".25"/>
<circle cx="235.9" cy="18.7" r=".25"/>
<circle cx="235.9" cy="19.9" r=".25"/>
<circle cx="30.5" cy="52" r=".25"/>
<circle cx="236.9" cy="23.7" r=".25"/>
<circle cx="231.1" cy="136.5" r=".25"/>
<circle cx="235.9" cy="23.7" r=".25"/>
<circle cx="54.3" cy="16.4" r=".25"/>
<circle cx="234.9" cy="136.5" r=".25"/>
<circle cx="263.5" cy="79" r=".25"/>
<circle cx="273.7" cy="84.1" r=".25"/>
<circle cx="31.4" cy="16.4" r=".25"/>
<circle cx="31.4" cy="21.5" r=".25"/>
<circle cx="35.2" cy="133.9" r=".25"/>
<circle cx="24.8" cy="128.8" r=".25"/>
<circle cx="214.9" cy="34.2" r=".25"/>
<circle cx="28.3" cy="128.8" r=".25"/>
<circle cx="183.2" cy="59.6" r=".25"/>
<circle cx="235.9" cy="63.4" r=".25"/>
<circle cx="235.9" cy="64.7" r=".25"/>
<circle cx="8.6" cy="22.8" r=".25"/>
<circle cx="184.1" cy="63.4" r=".25"/>
<circle cx="160.3" cy="141.2" r=".25"/>
<circle cx="160.3" cy="140.3" r=".25"/>
<circle cx="160.3" cy="139.3" r=".25"/>
<circle cx="183.2" cy="63.4" r=".25"/>
<circle cx="60.3" cy="22.2" r=".25"/>
<circle cx="17.8" cy="60.3" r=".25"/>
<circle cx="214.9" cy="73.9" r=".25"/>
<circle cx="183.2" cy="58.4" r=".25"/>
<circle cx="66.4" cy="16.4" r=".25"/>
<circle cx="261.6" cy="89.5" r=".25"/>
<circle cx="235.9" cy="76.4" r=".25"/>
<circle cx="214.9" cy="55.8" r=".25"/>
<circle cx="236.9" cy="63.4" r=".25"/>
<circle cx="16.2" cy="19" r=".25"/>
<circle cx="12.1" cy="19" r=".25"/>
<circle cx="16.2" cy="22.8" r=".25"/>
<circle cx="59.4" cy="111.4" r=".25"/>
<circle cx="235.9" cy="58.4" r=".25"/>
<circle cx="62.9" cy="110.1" r=".25"/>
<circle cx="235.9" cy="59.6" r=".25"/>
<circle cx="29.8" cy="16.4" r=".25"/>
</g>
<g fill="none" stroke="#000084" stroke-width=".13">
<path d="M40.3 18.4l.6 .6M40.9 18.4l-.6 .6M11.8 50.1l.6 .6M12.4 50.1l-.6 .6M253.7 97.1l.6 .6M254.3 97.1l-.6 .6M263.2 87.9l.6 .6M263.8 87.9l-.6 .6M35.3 127.3l.6 .6M35.9 127.3l-.6 .6M179.1 141.9l.6 .6M179.1 142.8l.6 .6"/>
<path d="M179.1 143.8l.6 .6M179.7 141.9l-.6 .6M179.7 142.8l-.6 .6M179.7 143.8l-.6 .6M186.4 144.7l.6 .6M187 144.7l-.6 .6M191.5 142.2l.6 .6M192.1 142.2l-.6 .6M161.3 171.4l.6 .6M161.3 172.7l.6 .6M161.3 161.2l.6 .6M161.9 171.4l-.6 .6"/>
<path d="M161.9 172.7l-.6 .6M161.9 161.2l-.6 .6M182.9 172.7l.6 .6M183.5 172.7l-.6 .6M267.3 173.6l.7 .6M267.3 172.3l.7 .7M268 173.6l-.7 .6M268 172.3l-.7 .7"/>
</g>
<use href="#words"/>
</svg>
